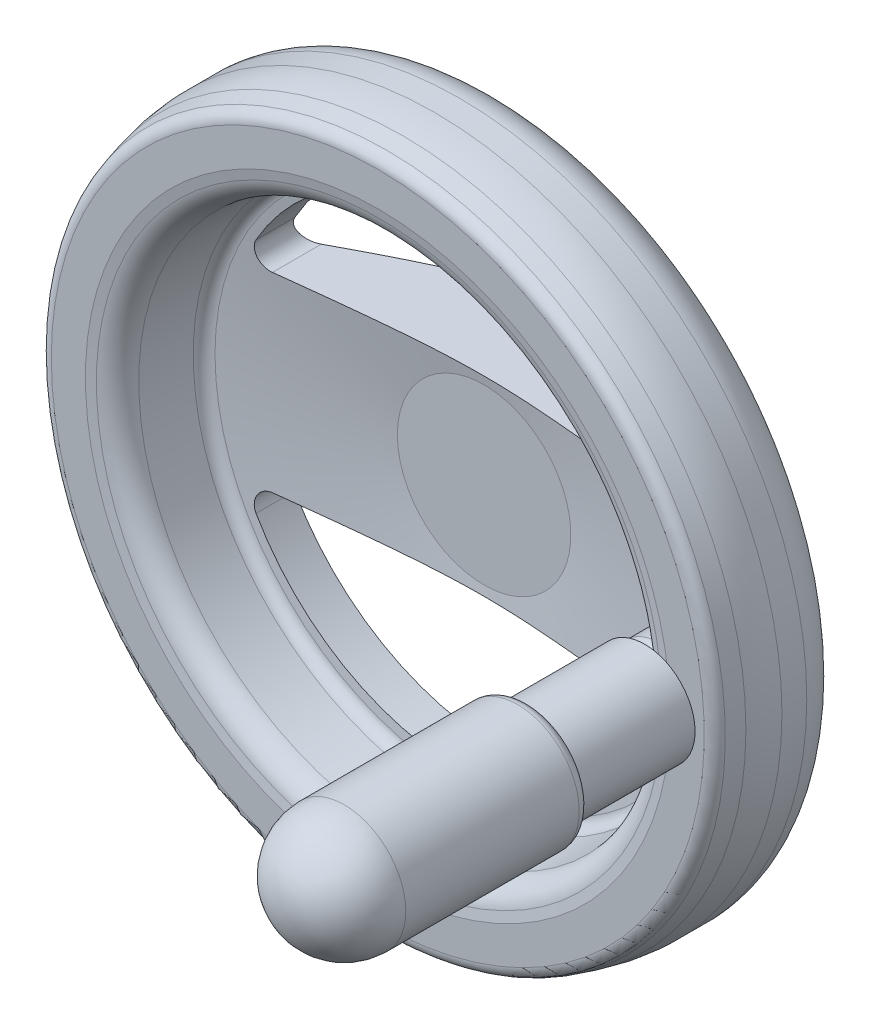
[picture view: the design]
ISO-10303-21;
HEADER;
FILE_DESCRIPTION(('STEP AP214'),'2;1');
FILE_NAME('part.step','',(''),(''),'','','');
FILE_SCHEMA(('AUTOMOTIVE_DESIGN { 1 0 10303 214 1 1 1 1 }'));
ENDSEC;
DATA;
#1=APPLICATION_CONTEXT('core data for automotive mechanical design processes');
#2=APPLICATION_PROTOCOL_DEFINITION('international standard','automotive_design',2000,#1);
#3=PRODUCT_CONTEXT('',#1,'mechanical');
#4=PRODUCT('Part','Part','',(#3));
#5=PRODUCT_RELATED_PRODUCT_CATEGORY('part','',(#4));
#6=PRODUCT_DEFINITION_FORMATION('','',#4);
#7=PRODUCT_DEFINITION_CONTEXT('part definition',#1,'design');
#8=PRODUCT_DEFINITION('design','',#6,#7);
#9=PRODUCT_DEFINITION_SHAPE('','',#8);
#10=(LENGTH_UNIT() NAMED_UNIT(*) SI_UNIT(.MILLI.,.METRE.));
#11=(NAMED_UNIT(*) PLANE_ANGLE_UNIT() SI_UNIT($,.RADIAN.));
#12=(NAMED_UNIT(*) SI_UNIT($,.STERADIAN.) SOLID_ANGLE_UNIT());
#13=UNCERTAINTY_MEASURE_WITH_UNIT(LENGTH_MEASURE(1.E-05),#10,'distance_accuracy_value','');
#14=(GEOMETRIC_REPRESENTATION_CONTEXT(3) GLOBAL_UNCERTAINTY_ASSIGNED_CONTEXT((#13)) GLOBAL_UNIT_ASSIGNED_CONTEXT((#10,
#11,#12)) REPRESENTATION_CONTEXT('',''));
#15=CARTESIAN_POINT('',(0.,0.,0.));
#16=DIRECTION('',(0.,0.,1.));
#17=DIRECTION('',(1.,0.,0.));
#18=AXIS2_PLACEMENT_3D('',#15,#16,#17);
#19=CARTESIAN_POINT('',(-3.6875,0.,22.));
#20=DIRECTION('',(0.,0.,-1.));
#21=DIRECTION('',(0.,1.,0.));
#22=AXIS2_PLACEMENT_3D('',#19,#20,#21);
#23=PLANE('',#22);
#24=CARTESIAN_POINT('',(0.,0.,21.9999999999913));
#25=DIRECTION('',(0.,0.,1.));
#26=DIRECTION('',(0.,-1.,0.));
#27=AXIS2_PLACEMENT_3D('',#24,#25,#26);
#28=CIRCLE('',#27,7.37499999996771);
#29=CARTESIAN_POINT('',(0.,-7.37499999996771,21.9999999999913));
#30=VERTEX_POINT('',#29);
#31=EDGE_CURVE('E227',#30,#30,#28,.F.);
#32=ORIENTED_EDGE('',*,*,#31,.T.);
#33=EDGE_LOOP('',(#32));
#34=FACE_BOUND('',#33,.T.);
#35=ADVANCED_FACE('F14',(#34),#23,.T.);
#36=CARTESIAN_POINT('',(0.,0.,22.0000000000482));
#37=DIRECTION('',(0.,0.,1.));
#38=DIRECTION('',(0.,-1.,0.));
#39=AXIS2_PLACEMENT_3D('',#36,#37,#38);
#40=CONICAL_SURFACE('',#39,7.37500000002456,0.785398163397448);
#41=ORIENTED_EDGE('',*,*,#31,.F.);
#42=EDGE_LOOP('',(#41));
#43=FACE_BOUND('',#42,.T.);
#44=CARTESIAN_POINT('',(0.,0.,20.625));
#45=DIRECTION('',(0.,0.,1.));
#46=DIRECTION('',(-1.,0.,0.));
#47=AXIS2_PLACEMENT_3D('',#44,#45,#46);
#48=CIRCLE('',#47,6.);
#49=CARTESIAN_POINT('',(-6.,0.,20.625));
#50=VERTEX_POINT('',#49);
#51=EDGE_CURVE('E230',#50,#50,#48,.F.);
#52=ORIENTED_EDGE('',*,*,#51,.T.);
#53=EDGE_LOOP('',(#52));
#54=FACE_BOUND('',#53,.T.);
#55=ADVANCED_FACE('F810',(#43,#54),#40,.F.);
#56=CARTESIAN_POINT('',(0.,0.,10.4125));
#57=DIRECTION('',(0.,0.,1.));
#58=DIRECTION('',(-1.,0.,0.));
#59=AXIS2_PLACEMENT_3D('',#56,#57,#58);
#60=CYLINDRICAL_SURFACE('',#59,6.);
#61=ORIENTED_EDGE('',*,*,#51,.F.);
#62=EDGE_LOOP('',(#61));
#63=FACE_BOUND('',#62,.T.);
#64=CARTESIAN_POINT('',(0.,0.,0.199999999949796));
#65=DIRECTION('',(0.,0.,-1.));
#66=DIRECTION('',(-1.,0.,0.));
#67=AXIS2_PLACEMENT_3D('',#64,#65,#66);
#68=CIRCLE('',#67,6.00000000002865);
#69=CARTESIAN_POINT('',(-6.00000000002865,0.,0.199999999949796));
#70=VERTEX_POINT('',#69);
#71=EDGE_CURVE('E226',#70,#70,#68,.T.);
#72=ORIENTED_EDGE('',*,*,#71,.T.);
#73=EDGE_LOOP('',(#72));
#74=FACE_BOUND('',#73,.T.);
#75=ADVANCED_FACE('F815',(#63,#74),#60,.F.);
#76=CARTESIAN_POINT('',(0.,0.,-5.68429783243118E-11));
#77=DIRECTION('',(0.,0.,-1.));
#78=DIRECTION('',(1.,0.,0.));
#79=AXIS2_PLACEMENT_3D('',#76,#77,#78);
#80=CONICAL_SURFACE('',#79,6.20000000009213,0.785398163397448);
#81=ORIENTED_EDGE('',*,*,#71,.F.);
#82=EDGE_LOOP('',(#81));
#83=FACE_BOUND('',#82,.T.);
#84=CARTESIAN_POINT('',(0.,0.,-5.68421109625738E-11));
#85=DIRECTION('',(0.,0.,-1.));
#86=DIRECTION('',(1.,0.,0.));
#87=AXIS2_PLACEMENT_3D('',#84,#85,#86);
#88=CIRCLE('',#87,6.20000000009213);
#89=CARTESIAN_POINT('',(6.20000000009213,0.,-5.68421109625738E-11));
#90=VERTEX_POINT('',#89);
#91=EDGE_CURVE('E223',#90,#90,#88,.F.);
#92=ORIENTED_EDGE('',*,*,#91,.F.);
#93=EDGE_LOOP('',(#92));
#94=FACE_BOUND('',#93,.T.);
#95=ADVANCED_FACE('F821',(#83,#94),#80,.F.);
#96=CARTESIAN_POINT('',(-8.6,0.,0.));
#97=DIRECTION('',(0.,0.,-1.));
#98=DIRECTION('',(1.,0.,0.));
#99=AXIS2_PLACEMENT_3D('',#96,#97,#98);
#100=PLANE('',#99);
#101=CARTESIAN_POINT('',(0.,0.,0.));
#102=DIRECTION('',(0.,0.,1.));
#103=DIRECTION('',(-1.,0.,0.));
#104=AXIS2_PLACEMENT_3D('',#101,#102,#103);
#105=CIRCLE('',#104,11.);
#106=CARTESIAN_POINT('',(-11.,0.,0.));
#107=VERTEX_POINT('',#106);
#108=EDGE_CURVE('E188',#107,#107,#105,.T.);
#109=ORIENTED_EDGE('',*,*,#108,.F.);
#110=EDGE_LOOP('',(#109));
#111=FACE_BOUND('',#110,.T.);
#112=ORIENTED_EDGE('',*,*,#91,.T.);
#113=EDGE_LOOP('',(#112));
#114=FACE_BOUND('',#113,.T.);
#115=ADVANCED_FACE('F824',(#111,#114),#100,.T.);
#116=CARTESIAN_POINT('',(0.,0.,0.1));
#117=DIRECTION('',(0.,0.,1.));
#118=DIRECTION('',(-1.,0.,0.));
#119=AXIS2_PLACEMENT_3D('',#116,#117,#118);
#120=CYLINDRICAL_SURFACE('',#119,11.);
#121=ORIENTED_EDGE('',*,*,#108,.T.);
#122=EDGE_LOOP('',(#121));
#123=FACE_BOUND('',#122,.T.);
#124=CARTESIAN_POINT('',(0.,0.,0.2));
#125=DIRECTION('',(0.,0.,1.));
#126=DIRECTION('',(-1.,0.,0.));
#127=AXIS2_PLACEMENT_3D('',#124,#125,#126);
#128=CIRCLE('',#127,11.);
#129=CARTESIAN_POINT('',(-11.,0.,0.2));
#130=VERTEX_POINT('',#129);
#131=EDGE_CURVE('E169',#130,#130,#128,.T.);
#132=ORIENTED_EDGE('',*,*,#131,.F.);
#133=EDGE_LOOP('',(#132));
#134=FACE_BOUND('',#133,.T.);
#135=ADVANCED_FACE('F212',(#123,#134),#120,.T.);
#136=CARTESIAN_POINT('',(-13.,0.,0.2));
#137=DIRECTION('',(0.,0.,-1.));
#138=DIRECTION('',(0.,1.,0.));
#139=AXIS2_PLACEMENT_3D('',#136,#137,#138);
#140=PLANE('',#139);
#141=CARTESIAN_POINT('',(0.,0.,0.2));
#142=DIRECTION('',(0.,0.,1.));
#143=DIRECTION('',(0.,-1.,0.));
#144=AXIS2_PLACEMENT_3D('',#141,#142,#143);
#145=CIRCLE('',#144,15.);
#146=CARTESIAN_POINT('',(0.,-15.,0.2));
#147=VERTEX_POINT('',#146);
#148=CARTESIAN_POINT('',(0.,15.,0.2));
#149=VERTEX_POINT('',#148);
#150=EDGE_CURVE('E572',#147,#149,#145,.T.);
#151=ORIENTED_EDGE('',*,*,#150,.F.);
#152=CARTESIAN_POINT('',(0.,0.,0.2));
#153=DIRECTION('',(0.,0.,1.));
#154=DIRECTION('',(-1.,0.,0.));
#155=AXIS2_PLACEMENT_3D('',#152,#153,#154);
#156=CIRCLE('',#155,15.);
#157=CARTESIAN_POINT('',(-15.,0.,0.2));
#158=VERTEX_POINT('',#157);
#159=EDGE_CURVE('E569',#158,#147,#156,.T.);
#160=ORIENTED_EDGE('',*,*,#159,.F.);
#161=CARTESIAN_POINT('',(0.,0.,0.2));
#162=DIRECTION('',(0.,0.,1.));
#163=DIRECTION('',(0.,1.,0.));
#164=AXIS2_PLACEMENT_3D('',#161,#162,#163);
#165=CIRCLE('',#164,15.);
#166=EDGE_CURVE('E537',#149,#158,#165,.T.);
#167=ORIENTED_EDGE('',*,*,#166,.F.);
#168=EDGE_LOOP('',(#151,#160,#167));
#169=FACE_BOUND('',#168,.T.);
#170=ORIENTED_EDGE('',*,*,#131,.T.);
#171=EDGE_LOOP('',(#170));
#172=FACE_BOUND('',#171,.T.);
#173=ADVANCED_FACE('F543',(#169,#172),#140,.T.);
#174=CARTESIAN_POINT('',(0.,0.,0.7));
#175=DIRECTION('',(0.,0.,-1.));
#176=DIRECTION('',(0.,1.,0.));
#177=AXIS2_PLACEMENT_3D('',#174,#175,#176);
#178=TOROIDAL_SURFACE('',#177,15.,0.5);
#179=CARTESIAN_POINT('',(0.,0.,0.7));
#180=DIRECTION('',(0.,0.,1.));
#181=DIRECTION('',(-1.,0.,0.));
#182=AXIS2_PLACEMENT_3D('',#179,#180,#181);
#183=CIRCLE('',#182,15.5);
#184=CARTESIAN_POINT('',(-15.5,0.,0.7));
#185=VERTEX_POINT('',#184);
#186=EDGE_CURVE('E605',#185,#185,#183,.T.);
#187=ORIENTED_EDGE('',*,*,#186,.F.);
#188=EDGE_LOOP('',(#187));
#189=FACE_BOUND('',#188,.T.);
#190=ORIENTED_EDGE('',*,*,#150,.T.);
#191=ORIENTED_EDGE('',*,*,#166,.T.);
#192=ORIENTED_EDGE('',*,*,#159,.T.);
#193=EDGE_LOOP('',(#190,#191,#192));
#194=FACE_BOUND('',#193,.T.);
#195=ADVANCED_FACE('F551',(#189,#194),#178,.T.);
#196=CARTESIAN_POINT('',(0.,0.,3.1));
#197=DIRECTION('',(0.,0.,1.));
#198=DIRECTION('',(-1.,0.,0.));
#199=AXIS2_PLACEMENT_3D('',#196,#197,#198);
#200=CYLINDRICAL_SURFACE('',#199,15.5);
#201=ORIENTED_EDGE('',*,*,#186,.T.);
#202=EDGE_LOOP('',(#201));
#203=FACE_BOUND('',#202,.T.);
#204=CARTESIAN_POINT('',(0.,0.,5.5));
#205=DIRECTION('',(0.,0.,1.));
#206=DIRECTION('',(-1.,0.,0.));
#207=AXIS2_PLACEMENT_3D('',#204,#205,#206);
#208=CIRCLE('',#207,15.5);
#209=CARTESIAN_POINT('',(-15.5,0.,5.5));
#210=VERTEX_POINT('',#209);
#211=EDGE_CURVE('E922',#210,#210,#208,.T.);
#212=ORIENTED_EDGE('',*,*,#211,.F.);
#213=EDGE_LOOP('',(#212));
#214=FACE_BOUND('',#213,.T.);
#215=ADVANCED_FACE('F259',(#203,#214),#200,.T.);
#216=CARTESIAN_POINT('',(0.,0.,29.3333333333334));
#217=DIRECTION('',(0.,0.,-1.));
#218=DIRECTION('',(0.,1.,0.));
#219=AXIS2_PLACEMENT_3D('',#216,#217,#218);
#220=TOROIDAL_SURFACE('',#219,54.6666666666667,7.33333333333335);
#221=CARTESIAN_POINT('',(0.,0.,22.));
#222=DIRECTION('',(0.,0.,1.));
#223=DIRECTION('',(0.,-1.,0.));
#224=AXIS2_PLACEMENT_3D('',#221,#222,#223);
#225=CIRCLE('',#224,54.6666666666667);
#226=CARTESIAN_POINT('',(0.,54.6666666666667,22.));
#227=VERTEX_POINT('',#226);
#228=CARTESIAN_POINT('',(0.,-54.6666666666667,22.));
#229=VERTEX_POINT('',#228);
#230=EDGE_CURVE('E239',#227,#229,#225,.F.);
#231=ORIENTED_EDGE('',*,*,#230,.F.);
#232=CARTESIAN_POINT('',(0.,0.,22.));
#233=DIRECTION('',(0.,0.,1.));
#234=DIRECTION('',(0.,1.,0.));
#235=AXIS2_PLACEMENT_3D('',#232,#233,#234);
#236=CIRCLE('',#235,54.6666666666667);
#237=CARTESIAN_POINT('',(-54.6666666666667,0.,22.));
#238=VERTEX_POINT('',#237);
#239=EDGE_CURVE('E287',#238,#227,#236,.F.);
#240=ORIENTED_EDGE('',*,*,#239,.F.);
#241=CARTESIAN_POINT('',(0.,0.,22.));
#242=DIRECTION('',(0.,0.,1.));
#243=DIRECTION('',(-1.,0.,0.));
#244=AXIS2_PLACEMENT_3D('',#241,#242,#243);
#245=CIRCLE('',#244,54.6666666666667);
#246=EDGE_CURVE('E276',#229,#238,#245,.F.);
#247=ORIENTED_EDGE('',*,*,#246,.F.);
#248=EDGE_LOOP('',(#231,#240,#247));
#249=FACE_BOUND('',#248,.T.);
#250=CARTESIAN_POINT('',(0.,0.,29.3333333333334));
#251=DIRECTION('',(0.,0.,-1.));
#252=DIRECTION('',(0.,1.,0.));
#253=AXIS2_PLACEMENT_3D('',#250,#251,#252);
#254=CIRCLE('',#253,62.);
#255=CARTESIAN_POINT('',(0.,62.,29.3333333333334));
#256=VERTEX_POINT('',#255);
#257=EDGE_CURVE('E300',#256,#256,#254,.T.);
#258=ORIENTED_EDGE('',*,*,#257,.T.);
#259=EDGE_LOOP('',(#258));
#260=FACE_BOUND('',#259,.T.);
#261=ADVANCED_FACE('F247',(#249,#260),#220,.T.);
#262=CARTESIAN_POINT('',(0.,0.,31.5518225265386));
#263=DIRECTION('',(0.,0.,1.));
#264=DIRECTION('',(-1.,0.,0.));
#265=AXIS2_PLACEMENT_3D('',#262,#263,#264);
#266=CYLINDRICAL_SURFACE('',#265,62.);
#267=CARTESIAN_POINT('',(0.,0.,33.770311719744));
#268=DIRECTION('',(0.,0.,1.));
#269=DIRECTION('',(-1.,0.,0.));
#270=AXIS2_PLACEMENT_3D('',#267,#268,#269);
#271=CIRCLE('',#270,62.);
#272=CARTESIAN_POINT('',(-62.,0.,33.770311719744));
#273=VERTEX_POINT('',#272);
#274=EDGE_CURVE('E931',#273,#273,#271,.F.);
#275=ORIENTED_EDGE('',*,*,#274,.T.);
#276=EDGE_LOOP('',(#275));
#277=FACE_BOUND('',#276,.T.);
#278=ORIENTED_EDGE('',*,*,#257,.F.);
#279=EDGE_LOOP('',(#278));
#280=FACE_BOUND('',#279,.T.);
#281=ADVANCED_FACE('F258',(#277,#280),#266,.T.);
#282=CARTESIAN_POINT('',(0.,0.,17.6));
#283=DIRECTION('',(0.,0.,-1.));
#284=DIRECTION('',(0.,1.,0.));
#285=AXIS2_PLACEMENT_3D('',#282,#283,#284);
#286=TOROIDAL_SURFACE('',#285,44.3996566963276,4.3999999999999);
#287=CARTESIAN_POINT('',(0.,0.,21.6825238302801));
#288=DIRECTION('',(0.,0.,-1.));
#289=DIRECTION('',(0.,1.,0.));
#290=AXIS2_PLACEMENT_3D('',#287,#288,#289);
#291=CIRCLE('',#290,42.7586206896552);
#292=CARTESIAN_POINT('',(-37.1502056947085,21.1698337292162,21.6825238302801));
#293=VERTEX_POINT('',#292);
#294=CARTESIAN_POINT('',(37.1502057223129,21.1698336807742,21.6825238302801));
#295=VERTEX_POINT('',#294);
#296=EDGE_CURVE('E310',#293,#295,#291,.T.);
#297=ORIENTED_EDGE('',*,*,#296,.F.);
#298=CARTESIAN_POINT('',(-37.4658577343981,19.305357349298,21.3797465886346));
#299=CARTESIAN_POINT('',(-37.477991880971,19.3710035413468,21.4040912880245));
#300=CARTESIAN_POINT('',(-37.4878240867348,19.4377213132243,21.4266745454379));
#301=CARTESIAN_POINT('',(-37.5026165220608,19.572709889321,21.4685151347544));
#302=CARTESIAN_POINT('',(-37.5075775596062,19.6409804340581,21.4877730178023));
#303=CARTESIAN_POINT('',(-37.5123633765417,19.7784953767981,21.5231648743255));
#304=CARTESIAN_POINT('',(-37.5121889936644,19.8477396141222,21.5392993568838));
#305=CARTESIAN_POINT('',(-37.5065616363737,19.9866080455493,21.5686657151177));
#306=CARTESIAN_POINT('',(-37.5011087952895,20.0562322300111,21.5818976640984));
#307=CARTESIAN_POINT('',(-37.476687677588,20.2648369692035,21.6175724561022));
#308=CARTESIAN_POINT('',(-37.4496606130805,20.4036511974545,21.6360193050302));
#309=CARTESIAN_POINT('',(-37.3743306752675,20.6760722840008,21.6636613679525));
#310=CARTESIAN_POINT('',(-37.3260665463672,20.8096881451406,21.6728733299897));
#311=CARTESIAN_POINT('',(-37.250048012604,20.9782012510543,21.6794580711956));
#312=CARTESIAN_POINT('',(-37.2313331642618,21.0172035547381,21.6806098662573));
#313=CARTESIAN_POINT('',(-37.1921088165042,21.0942437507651,21.6821419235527));
#314=CARTESIAN_POINT('',(-37.1716017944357,21.1322828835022,21.6825232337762));
#315=CARTESIAN_POINT('',(-37.1502056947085,21.1698337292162,21.6825238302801));
#316=B_SPLINE_CURVE_WITH_KNOTS('',3,(#298,#299,#300,#301,#302,#303,#304,#305,#306,#307,#308,
#309,#310,#311,#312,#313,#314,#315),.UNSPECIFIED.,.F.,.F.,(4,2,2,2,2,2,2,2,4),(0.,
0.213099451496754,0.426163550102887,0.639192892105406,0.852216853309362,1.27795500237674,
1.70291964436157,1.83270697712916,1.96231765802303),.UNSPECIFIED.);
#317=CARTESIAN_POINT('',(-37.465857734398,19.3053573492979,21.3797465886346));
#318=VERTEX_POINT('',#317);
#319=EDGE_CURVE('E350',#318,#293,#316,.T.);
#320=ORIENTED_EDGE('',*,*,#319,.F.);
#321=CARTESIAN_POINT('',(0.,0.,21.3797465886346));
#322=DIRECTION('',(0.,0.,-1.));
#323=DIRECTION('',(0.,1.,0.));
#324=AXIS2_PLACEMENT_3D('',#321,#322,#323);
#325=CIRCLE('',#324,42.1472100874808);
#326=CARTESIAN_POINT('',(-37.465857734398,-19.3053573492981,21.3797465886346));
#327=VERTEX_POINT('',#326);
#328=EDGE_CURVE('E334',#327,#318,#325,.T.);
#329=ORIENTED_EDGE('',*,*,#328,.F.);
#330=CARTESIAN_POINT('',(-37.1502057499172,-21.1698336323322,21.68252383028));
#331=CARTESIAN_POINT('',(-37.1857308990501,-21.1075115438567,21.6825145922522));
#332=CARTESIAN_POINT('',(-37.2188054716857,-21.0437931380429,21.6814700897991));
#333=CARTESIAN_POINT('',(-37.2798689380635,-20.9140276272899,21.6772435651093));
#334=CARTESIAN_POINT('',(-37.3078575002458,-20.8479803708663,21.6740614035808));
#335=CARTESIAN_POINT('',(-37.3585995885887,-20.713924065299,21.6654858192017));
#336=CARTESIAN_POINT('',(-37.3813448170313,-20.6459120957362,21.660088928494));
#337=CARTESIAN_POINT('',(-37.4214185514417,-20.5085362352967,21.646954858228));
#338=CARTESIAN_POINT('',(-37.4387474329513,-20.4391724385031,21.6392178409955));
#339=CARTESIAN_POINT('',(-37.4679400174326,-20.2995236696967,21.6212232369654));
#340=CARTESIAN_POINT('',(-37.4797961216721,-20.2292375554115,21.6109621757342));
#341=CARTESIAN_POINT('',(-37.4980012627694,-20.0884021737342,21.5877222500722));
#342=CARTESIAN_POINT('',(-37.5043504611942,-20.0178529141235,21.5747434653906));
#343=CARTESIAN_POINT('',(-37.5116013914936,-19.8772479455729,21.5458799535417));
#344=CARTESIAN_POINT('',(-37.5125161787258,-19.8071914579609,21.5300022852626));
#345=CARTESIAN_POINT('',(-37.5090819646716,-19.6680289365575,21.4950986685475));
#346=CARTESIAN_POINT('',(-37.5047358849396,-19.5989223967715,21.4760744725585));
#347=CARTESIAN_POINT('',(-37.494063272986,-19.4924910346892,21.4438281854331));
#348=CARTESIAN_POINT('',(-37.4894634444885,-19.4546310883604,21.4317625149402));
#349=CARTESIAN_POINT('',(-37.4787676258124,-19.379522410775,21.4065646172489));
#350=CARTESIAN_POINT('',(-37.4726730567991,-19.342273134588,21.393433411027));
#351=CARTESIAN_POINT('',(-37.465857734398,-19.3053573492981,21.3797465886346));
#352=B_SPLINE_CURVE_WITH_KNOTS('',3,(#330,#331,#332,#333,#334,#335,#336,#337,#338,#339,#340,
#341,#342,#343,#344,#345,#346,#347,#348,#349,#350,#351),.UNSPECIFIED.,.F.,.F.,(4,2,2,2,2,2,2,2,
2,2,4),(0.,0.215145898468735,0.43030581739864,0.645803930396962,0.861287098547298,
1.07706856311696,1.29284369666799,1.50810025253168,1.72323732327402,1.84319972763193,
1.96304851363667),.UNSPECIFIED.);
#353=CARTESIAN_POINT('',(-37.1502057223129,-21.1698336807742,21.6825238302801));
#354=VERTEX_POINT('',#353);
#355=EDGE_CURVE('E342',#354,#327,#352,.T.);
#356=ORIENTED_EDGE('',*,*,#355,.F.);
#357=CARTESIAN_POINT('',(0.,0.,21.6825238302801));
#358=DIRECTION('',(0.,0.,-1.));
#359=DIRECTION('',(0.,1.,0.));
#360=AXIS2_PLACEMENT_3D('',#357,#358,#359);
#361=CIRCLE('',#360,42.7586206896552);
#362=CARTESIAN_POINT('',(37.1502056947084,-21.1698337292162,21.68252383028));
#363=VERTEX_POINT('',#362);
#364=EDGE_CURVE('E297',#363,#354,#361,.T.);
#365=ORIENTED_EDGE('',*,*,#364,.F.);
#366=CARTESIAN_POINT('',(37.465857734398,-19.305357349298,21.3797465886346));
#367=CARTESIAN_POINT('',(37.4779918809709,-19.3710035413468,21.4040912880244));
#368=CARTESIAN_POINT('',(37.4878240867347,-19.4377213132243,21.4266745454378));
#369=CARTESIAN_POINT('',(37.5026165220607,-19.572709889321,21.4685151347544));
#370=CARTESIAN_POINT('',(37.5075775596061,-19.6409804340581,21.4877730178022));
#371=CARTESIAN_POINT('',(37.5123633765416,-19.7784953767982,21.5231648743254));
#372=CARTESIAN_POINT('',(37.5121889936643,-19.8477396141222,21.5392993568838));
#373=CARTESIAN_POINT('',(37.5065616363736,-19.9866080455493,21.5686657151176));
#374=CARTESIAN_POINT('',(37.5011087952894,-20.0562322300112,21.5818976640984));
#375=CARTESIAN_POINT('',(37.4766876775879,-20.2648369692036,21.6175724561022));
#376=CARTESIAN_POINT('',(37.4496606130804,-20.4036511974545,21.6360193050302));
#377=CARTESIAN_POINT('',(37.3743306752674,-20.6760722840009,21.6636613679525));
#378=CARTESIAN_POINT('',(37.326066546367,-20.8096881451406,21.6728733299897));
#379=CARTESIAN_POINT('',(37.2500480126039,-20.9782012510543,21.6794580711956));
#380=CARTESIAN_POINT('',(37.2313331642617,-21.0172035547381,21.6806098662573));
#381=CARTESIAN_POINT('',(37.1921088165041,-21.0942437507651,21.6821419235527));
#382=CARTESIAN_POINT('',(37.1716017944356,-21.1322828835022,21.6825232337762));
#383=CARTESIAN_POINT('',(37.1502056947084,-21.1698337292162,21.68252383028));
#384=B_SPLINE_CURVE_WITH_KNOTS('',3,(#366,#367,#368,#369,#370,#371,#372,#373,#374,#375,#376,
#377,#378,#379,#380,#381,#382,#383),.UNSPECIFIED.,.F.,.F.,(4,2,2,2,2,2,2,2,4),(0.,
0.213099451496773,0.426163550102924,0.639192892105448,0.852216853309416,1.2779550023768,
1.70291964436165,1.83270697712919,1.96231765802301),.UNSPECIFIED.);
#385=CARTESIAN_POINT('',(37.465857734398,-19.305357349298,21.3797465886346));
#386=VERTEX_POINT('',#385);
#387=EDGE_CURVE('E301',#386,#363,#384,.T.);
#388=ORIENTED_EDGE('',*,*,#387,.F.);
#389=CARTESIAN_POINT('',(0.,0.,21.3797465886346));
#390=DIRECTION('',(0.,0.,-1.));
#391=DIRECTION('',(0.,1.,0.));
#392=AXIS2_PLACEMENT_3D('',#389,#390,#391);
#393=CIRCLE('',#392,42.1472100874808);
#394=CARTESIAN_POINT('',(37.4658577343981,19.305357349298,21.3797465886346));
#395=VERTEX_POINT('',#394);
#396=EDGE_CURVE('E304',#395,#386,#393,.T.);
#397=ORIENTED_EDGE('',*,*,#396,.F.);
#398=CARTESIAN_POINT('',(37.1502057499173,21.1698336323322,21.6825238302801));
#399=CARTESIAN_POINT('',(37.1857308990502,21.1075115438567,21.6825145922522));
#400=CARTESIAN_POINT('',(37.2188054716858,21.043793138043,21.6814700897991));
#401=CARTESIAN_POINT('',(37.2798689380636,20.9140276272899,21.6772435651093));
#402=CARTESIAN_POINT('',(37.3078575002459,20.8479803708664,21.6740614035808));
#403=CARTESIAN_POINT('',(37.3585995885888,20.713924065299,21.6654858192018));
#404=CARTESIAN_POINT('',(37.3813448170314,20.6459120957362,21.660088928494));
#405=CARTESIAN_POINT('',(37.4214185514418,20.5085362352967,21.6469548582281));
#406=CARTESIAN_POINT('',(37.4387474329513,20.4391724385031,21.6392178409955));
#407=CARTESIAN_POINT('',(37.4679400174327,20.2995236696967,21.6212232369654));
#408=CARTESIAN_POINT('',(37.4797961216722,20.2292375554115,21.6109621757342));
#409=CARTESIAN_POINT('',(37.4980012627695,20.0884021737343,21.5877222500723));
#410=CARTESIAN_POINT('',(37.5043504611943,20.0178529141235,21.5747434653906));
#411=CARTESIAN_POINT('',(37.5116013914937,19.877247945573,21.5458799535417));
#412=CARTESIAN_POINT('',(37.5125161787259,19.807191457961,21.5300022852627));
#413=CARTESIAN_POINT('',(37.5090819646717,19.6680289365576,21.4950986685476));
#414=CARTESIAN_POINT('',(37.5047358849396,19.5989223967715,21.4760744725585));
#415=CARTESIAN_POINT('',(37.4940632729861,19.4924910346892,21.4438281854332));
#416=CARTESIAN_POINT('',(37.4894634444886,19.4546310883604,21.4317625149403));
#417=CARTESIAN_POINT('',(37.4787676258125,19.3795224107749,21.4065646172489));
#418=CARTESIAN_POINT('',(37.4726730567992,19.3422731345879,21.393433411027));
#419=CARTESIAN_POINT('',(37.4658577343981,19.305357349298,21.3797465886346));
#420=B_SPLINE_CURVE_WITH_KNOTS('',3,(#398,#399,#400,#401,#402,#403,#404,#405,#406,#407,#408,
#409,#410,#411,#412,#413,#414,#415,#416,#417,#418,#419),.UNSPECIFIED.,.F.,.F.,(4,2,2,2,2,2,2,2,
2,2,4),(0.,0.215145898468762,0.430305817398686,0.645803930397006,0.861287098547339,
1.07706856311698,1.29284369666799,1.50810025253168,1.72323732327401,1.843199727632,
1.96304851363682),.UNSPECIFIED.);
#421=EDGE_CURVE('E307',#295,#395,#420,.T.);
#422=ORIENTED_EDGE('',*,*,#421,.F.);
#423=EDGE_LOOP('',(#297,#320,#329,#356,#365,#388,#397,#422));
#424=FACE_BOUND('',#423,.T.);
#425=CARTESIAN_POINT('',(0.,0.,21.9999999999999));
#426=DIRECTION('',(0.,0.,-1.));
#427=DIRECTION('',(0.,-1.,0.));
#428=AXIS2_PLACEMENT_3D('',#425,#426,#427);
#429=CIRCLE('',#428,44.3996566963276);
#430=CARTESIAN_POINT('',(0.,44.3996566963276,22.));
#431=VERTEX_POINT('',#430);
#432=CARTESIAN_POINT('',(0.,-44.3996566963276,22.));
#433=VERTEX_POINT('',#432);
#434=EDGE_CURVE('E986',#431,#433,#429,.F.);
#435=ORIENTED_EDGE('',*,*,#434,.F.);
#436=CARTESIAN_POINT('',(0.,0.,21.9999999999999));
#437=DIRECTION('',(0.,0.,-1.));
#438=DIRECTION('',(0.,1.,0.));
#439=AXIS2_PLACEMENT_3D('',#436,#437,#438);
#440=CIRCLE('',#439,44.3996566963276);
#441=CARTESIAN_POINT('',(44.2383861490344,3.78083399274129,22.));
#442=VERTEX_POINT('',#441);
#443=EDGE_CURVE('E488',#442,#431,#440,.F.);
#444=ORIENTED_EDGE('',*,*,#443,.F.);
#445=CARTESIAN_POINT('',(0.,0.,21.9999999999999));
#446=DIRECTION('',(0.,0.,-1.));
#447=DIRECTION('',(0.996367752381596,0.0851545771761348,0.));
#448=AXIS2_PLACEMENT_3D('',#445,#446,#447);
#449=CIRCLE('',#448,44.3996566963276);
#450=CARTESIAN_POINT('',(44.2383861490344,-3.78083399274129,22.));
#451=VERTEX_POINT('',#450);
#452=EDGE_CURVE('E313',#451,#442,#449,.F.);
#453=ORIENTED_EDGE('',*,*,#452,.F.);
#454=CARTESIAN_POINT('',(0.,0.,21.9999999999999));
#455=DIRECTION('',(0.,0.,-1.));
#456=DIRECTION('',(0.996367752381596,-0.0851545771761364,0.));
#457=AXIS2_PLACEMENT_3D('',#454,#455,#456);
#458=CIRCLE('',#457,44.3996566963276);
#459=EDGE_CURVE('E322',#433,#451,#458,.F.);
#460=ORIENTED_EDGE('',*,*,#459,.F.);
#461=EDGE_LOOP('',(#435,#444,#453,#460));
#462=FACE_BOUND('',#461,.T.);
#463=ADVANCED_FACE('F262',(#424,#462),#286,.F.);
#464=CARTESIAN_POINT('',(0.,0.,21.3797465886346));
#465=DIRECTION('',(0.,0.,1.));
#466=DIRECTION('',(-1.,0.,0.));
#467=AXIS2_PLACEMENT_3D('',#464,#465,#466);
#468=CONICAL_SURFACE('',#467,42.1472100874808,1.03337831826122);
#469=ORIENTED_EDGE('',*,*,#211,.T.);
#470=EDGE_LOOP('',(#469));
#471=FACE_BOUND('',#470,.T.);
#472=CARTESIAN_POINT('',(-34.7560813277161,-17.05,19.3331471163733));
#473=CARTESIAN_POINT('',(-34.9642160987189,-17.0500388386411,19.4445654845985));
#474=CARTESIAN_POINT('',(-35.1694190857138,-17.0735554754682,19.5606672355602));
#475=CARTESIAN_POINT('',(-35.5667554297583,-17.164089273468,19.7972740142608));
#476=CARTESIAN_POINT('',(-35.7589160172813,-17.2310125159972,19.9177690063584));
#477=CARTESIAN_POINT('',(-36.099678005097,-17.3933837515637,20.1427185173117));
#478=CARTESIAN_POINT('',(-36.250675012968,-17.4838625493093,20.2471778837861));
#479=CARTESIAN_POINT('',(-36.5340722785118,-17.6930027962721,20.4534650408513));
#480=CARTESIAN_POINT('',(-36.6664589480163,-17.8116846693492,20.5552908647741));
#481=CARTESIAN_POINT('',(-36.9097263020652,-18.0770520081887,20.7549142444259));
#482=CARTESIAN_POINT('',(-37.0202464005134,-18.2241386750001,20.8526261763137));
#483=CARTESIAN_POINT('',(-37.1636021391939,-18.4618665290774,20.9920574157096));
#484=CARTESIAN_POINT('',(-37.2076243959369,-18.5438882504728,21.0373125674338));
#485=CARTESIAN_POINT('',(-37.2875839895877,-18.7131623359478,21.1250514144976));
#486=CARTESIAN_POINT('',(-37.3235269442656,-18.8004110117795,21.1675370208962));
#487=CARTESIAN_POINT('',(-37.378644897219,-18.9568600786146,21.2389212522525));
#488=CARTESIAN_POINT('',(-37.3997621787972,-19.0250543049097,21.2685416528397));
#489=CARTESIAN_POINT('',(-37.4367840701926,-19.163634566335,21.3257302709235));
#490=CARTESIAN_POINT('',(-37.4526913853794,-19.2340194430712,21.353299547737));
#491=CARTESIAN_POINT('',(-37.465857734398,-19.3053573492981,21.3797465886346));
#492=B_SPLINE_CURVE_WITH_KNOTS('',3,(#472,#473,#474,#475,#476,#477,#478,#479,#480,#481,#482,
#483,#484,#485,#486,#487,#488,#489,#490,#491),.UNSPECIFIED.,.F.,.F.,(4,2,2,2,2,2,2,2,2,4),(0.,
0.706568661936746,1.41161360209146,2.0230154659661,2.63486144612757,3.25608193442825,
3.5662093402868,3.87612043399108,4.1077705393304,4.33930016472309),.UNSPECIFIED.);
#493=CARTESIAN_POINT('',(-34.7560813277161,-17.05,19.3331471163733));
#494=VERTEX_POINT('',#493);
#495=EDGE_CURVE('E1469',#494,#327,#492,.T.);
#496=ORIENTED_EDGE('',*,*,#495,.T.);
#497=ORIENTED_EDGE('',*,*,#328,.T.);
#498=CARTESIAN_POINT('',(-37.465857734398,19.3053573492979,21.3797465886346));
#499=CARTESIAN_POINT('',(-37.45063462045,19.2228937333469,21.3491732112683));
#500=CARTESIAN_POINT('',(-37.4317600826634,19.1417288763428,21.3171129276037));
#501=CARTESIAN_POINT('',(-37.3871473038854,18.9825042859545,21.2503457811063));
#502=CARTESIAN_POINT('',(-37.36141437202,18.9044422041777,21.2156409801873));
#503=CARTESIAN_POINT('',(-37.2748626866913,18.6763284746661,21.1083733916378));
#504=CARTESIAN_POINT('',(-37.2045125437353,18.5314258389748,21.0323117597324));
#505=CARTESIAN_POINT('',(-37.0423053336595,18.2591559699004,20.8736588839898));
#506=CARTESIAN_POINT('',(-36.9505105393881,18.1317396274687,20.7910869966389));
#507=CARTESIAN_POINT('',(-36.7485268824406,17.8957384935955,20.6211835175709));
#508=CARTESIAN_POINT('',(-36.6383094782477,17.7871834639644,20.5338446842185));
#509=CARTESIAN_POINT('',(-36.390008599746,17.5801946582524,20.346903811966));
#510=CARTESIAN_POINT('',(-36.2502031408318,17.4841040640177,20.2469929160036));
#511=CARTESIAN_POINT('',(-35.9559631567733,17.319233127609,20.0463793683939));
#512=CARTESIAN_POINT('',(-35.8015348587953,17.2504412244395,19.9456770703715));
#513=CARTESIAN_POINT('',(-35.5007531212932,17.1483578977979,19.7578042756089));
#514=CARTESIAN_POINT('',(-35.3556140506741,17.1118238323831,19.6704453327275));
#515=CARTESIAN_POINT('',(-35.0595338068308,17.0626556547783,19.4989251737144));
#516=CARTESIAN_POINT('',(-34.9085924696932,17.050022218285,19.4147640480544));
#517=CARTESIAN_POINT('',(-34.7560813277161,17.05,19.3331471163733));
#518=B_SPLINE_CURVE_WITH_KNOTS('',3,(#498,#499,#500,#501,#502,#503,#504,#505,#506,#507,#508,
#509,#510,#511,#512,#513,#514,#515,#516,#517),.UNSPECIFIED.,.F.,.F.,(4,2,2,2,2,2,2,2,2,4),(0.,
0.267554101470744,0.53490168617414,1.06663180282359,1.59683661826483,2.12787060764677,
2.71600119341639,3.30388243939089,3.82204375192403,4.34021971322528),.UNSPECIFIED.);
#519=CARTESIAN_POINT('',(-34.7560813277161,17.05,19.3331471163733));
#520=VERTEX_POINT('',#519);
#521=EDGE_CURVE('E380',#318,#520,#518,.T.);
#522=ORIENTED_EDGE('',*,*,#521,.T.);
#523=CARTESIAN_POINT('',(-34.7560813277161,17.05,19.3331471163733));
#524=CARTESIAN_POINT('',(-33.9725683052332,17.05,18.9140040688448));
#525=CARTESIAN_POINT('',(-33.187944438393,17.05,18.4969215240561));
#526=CARTESIAN_POINT('',(-31.6159567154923,17.05,17.667875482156));
#527=CARTESIAN_POINT('',(-30.8285927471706,17.05,17.2559121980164));
#528=CARTESIAN_POINT('',(-29.2495677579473,17.05,16.4375656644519));
#529=CARTESIAN_POINT('',(-28.4579022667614,17.05,16.0311910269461));
#530=CARTESIAN_POINT('',(-26.8707444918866,17.05,15.2260017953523));
#531=CARTESIAN_POINT('',(-26.0752522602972,17.05,14.827187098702));
#532=CARTESIAN_POINT('',(-24.4369579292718,17.05,14.0177947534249));
#533=CARTESIAN_POINT('',(-23.5939019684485,17.05,13.6077295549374));
#534=CARTESIAN_POINT('',(-21.9014905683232,17.05,12.8007036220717));
#535=CARTESIAN_POINT('',(-21.052134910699,17.05,12.4037433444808));
#536=CARTESIAN_POINT('',(-19.3461264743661,17.05,11.626846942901));
#537=CARTESIAN_POINT('',(-18.4894774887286,17.05,11.2469025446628));
#538=CARTESIAN_POINT('',(-17.1974661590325,17.05,10.6934878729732));
#539=CARTESIAN_POINT('',(-16.7656332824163,17.05,10.5117708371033));
#540=CARTESIAN_POINT('',(-15.8993625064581,17.05,10.1546646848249));
#541=CARTESIAN_POINT('',(-15.4649246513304,17.05,9.97927546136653));
#542=CARTESIAN_POINT('',(-14.5301471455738,17.05,9.61092120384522));
#543=CARTESIAN_POINT('',(-14.0293621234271,17.05,9.41908211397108));
#544=CARTESIAN_POINT('',(-13.0236598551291,17.05,9.04659617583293));
#545=CARTESIAN_POINT('',(-12.5187427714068,17.05,8.86594888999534));
#546=CARTESIAN_POINT('',(-11.5042481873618,17.05,8.51776826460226));
#547=CARTESIAN_POINT('',(-10.9946697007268,17.05,8.35023777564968));
#548=CARTESIAN_POINT('',(-9.9707227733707,17.05,8.0306459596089));
#549=CARTESIAN_POINT('',(-9.45635433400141,17.05,7.87858462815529));
#550=CARTESIAN_POINT('',(-7.92620850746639,17.05,7.45517806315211));
#551=CARTESIAN_POINT('',(-6.90297443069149,17.05,7.20940813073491));
#552=CARTESIAN_POINT('',(-5.3551607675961,17.05,6.90909796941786));
#553=CARTESIAN_POINT('',(-4.83711291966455,17.05,6.82039061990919));
#554=CARTESIAN_POINT('',(-3.79725745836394,17.05,6.66828978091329));
#555=CARTESIAN_POINT('',(-3.27544988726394,17.05,6.60489600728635));
#556=CARTESIAN_POINT('',(-2.21924330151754,17.05,6.50459293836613));
#557=CARTESIAN_POINT('',(-1.68479371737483,17.05,6.46821090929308));
#558=CARTESIAN_POINT('',(-0.614687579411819,17.05,6.42530779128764));
#559=CARTESIAN_POINT('',(-0.0790310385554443,17.05,6.41878638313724));
#560=CARTESIAN_POINT('',(0.991781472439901,17.05,6.43586040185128));
#561=CARTESIAN_POINT('',(1.52693745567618,17.05,6.45945501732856));
#562=CARTESIAN_POINT('',(2.5951483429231,17.05,6.53584590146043));
#563=CARTESIAN_POINT('',(3.12820319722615,17.05,6.58864285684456));
#564=CARTESIAN_POINT('',(4.20204910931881,17.05,6.72293286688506));
#565=CARTESIAN_POINT('',(4.74276684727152,17.05,6.8050065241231));
#566=CARTESIAN_POINT('',(5.81967745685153,17.05,6.99488444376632));
#567=CARTESIAN_POINT('',(6.35586984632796,17.05,7.10269141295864));
#568=CARTESIAN_POINT('',(7.42338587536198,17.05,7.34102353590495));
#569=CARTESIAN_POINT('',(7.95470727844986,17.05,7.4715586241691));
#570=CARTESIAN_POINT('',(9.0121030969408,17.05,7.75225748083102));
#571=CARTESIAN_POINT('',(9.53817749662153,17.05,7.90242130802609));
#572=CARTESIAN_POINT('',(10.621187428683,17.05,8.23042811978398));
#573=CARTESIAN_POINT('',(11.1777598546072,17.05,8.40946399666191));
#574=CARTESIAN_POINT('',(12.2854805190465,17.05,8.78365072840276));
#575=CARTESIAN_POINT('',(12.8366283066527,17.05,8.97880291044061));
#576=CARTESIAN_POINT('',(13.9341401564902,17.05,9.38267214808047));
#577=CARTESIAN_POINT('',(14.4805023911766,17.05,9.59139414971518));
#578=CARTESIAN_POINT('',(15.5687390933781,17.05,10.0201486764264));
#579=CARTESIAN_POINT('',(16.1106136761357,17.05,10.2401809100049));
#580=CARTESIAN_POINT('',(17.1914207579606,17.05,10.6901844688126));
#581=CARTESIAN_POINT('',(17.7303456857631,17.05,10.9201739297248));
#582=CARTESIAN_POINT('',(18.8046810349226,17.05,11.3882094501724));
#583=CARTESIAN_POINT('',(19.3400914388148,17.05,11.6262555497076));
#584=CARTESIAN_POINT('',(20.4077124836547,17.05,12.1091289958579));
#585=CARTESIAN_POINT('',(20.9399237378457,17.05,12.3539549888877));
#586=CARTESIAN_POINT('',(22.0016218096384,17.05,12.8494305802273));
#587=CARTESIAN_POINT('',(22.531108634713,17.05,13.1000801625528));
#588=CARTESIAN_POINT('',(24.049321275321,17.05,13.8275438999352));
#589=CARTESIAN_POINT('',(25.0350550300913,17.05,14.3106040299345));
#590=CARTESIAN_POINT('',(26.999950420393,17.05,15.2899855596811));
#591=CARTESIAN_POINT('',(27.9791116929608,17.05,15.7863076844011));
#592=CARTESIAN_POINT('',(29.9270073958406,17.05,16.7865810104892));
#593=CARTESIAN_POINT('',(30.8957695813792,17.05,17.2904782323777));
#594=CARTESIAN_POINT('',(32.3456864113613,17.05,18.0523103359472));
#595=CARTESIAN_POINT('',(32.828426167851,17.05,18.307237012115));
#596=CARTESIAN_POINT('',(33.7929469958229,17.05,18.818891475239));
#597=CARTESIAN_POINT('',(34.2747280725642,17.05,19.0756192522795));
#598=CARTESIAN_POINT('',(34.7560813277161,17.05,19.3331471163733));
#599=B_SPLINE_CURVE_WITH_KNOTS('',3,(#523,#524,#525,#526,#527,#528,#529,#530,#531,#532,#533,
#534,#535,#536,#537,#538,#539,#540,#541,#542,#543,#544,#545,#546,#547,#548,#549,#550,#551,#552,
#553,#554,#555,#556,#557,#558,#559,#560,#561,#562,#563,#564,#565,#566,#567,#568,#569,#570,#571,
#572,#573,#574,#575,#576,#577,#578,#579,#580,#581,#582,#583,#584,#585,#586,#587,#588,#589,#590,
#591,#592,#593,#594,#595,#596,#597,#598),.UNSPECIFIED.,.F.,.F.,(4,2,2,2,2,2,2,2,2,2,2,2,2,2,2,2,
2,2,2,2,2,2,2,2,2,2,2,2,2,2,2,2,2,2,2,2,2,4),(0.,2.66574670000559,5.33160393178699,
8.00119036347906,10.6707405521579,13.4831341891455,16.2956257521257,19.1067345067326,
20.5122208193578,21.9176833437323,23.5263827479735,25.1350192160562,26.7440043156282,
28.3529889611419,31.5061153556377,33.0823752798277,34.6586175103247,36.2648724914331,
37.8711103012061,39.4773048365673,41.0835371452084,42.7235772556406,44.3637899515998,
46.0047213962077,47.6456577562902,49.3993406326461,51.1531680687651,52.9076383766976,
54.6620634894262,56.4198308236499,58.1776068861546,59.9350345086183,61.6924573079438,
64.9855082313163,68.2787395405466,71.5546180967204,73.192365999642,74.830104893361),.UNSPECIFIED.);
#600=CARTESIAN_POINT('',(34.7560813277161,17.05,19.3331471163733));
#601=VERTEX_POINT('',#600);
#602=EDGE_CURVE('E1445',#520,#601,#599,.T.);
#603=ORIENTED_EDGE('',*,*,#602,.T.);
#604=CARTESIAN_POINT('',(34.7560813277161,17.05,19.3331471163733));
#605=CARTESIAN_POINT('',(34.9642160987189,17.0500388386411,19.4445654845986));
#606=CARTESIAN_POINT('',(35.1694190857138,17.0735554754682,19.5606672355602));
#607=CARTESIAN_POINT('',(35.5667554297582,17.164089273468,19.7972740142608));
#608=CARTESIAN_POINT('',(35.7589160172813,17.2310125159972,19.9177690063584));
#609=CARTESIAN_POINT('',(36.099678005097,17.3933837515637,20.1427185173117));
#610=CARTESIAN_POINT('',(36.2506750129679,17.4838625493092,20.2471778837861));
#611=CARTESIAN_POINT('',(36.5340722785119,17.6930027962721,20.4534650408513));
#612=CARTESIAN_POINT('',(36.6664589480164,17.8116846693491,20.5552908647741));
#613=CARTESIAN_POINT('',(36.9097263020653,18.0770520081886,20.7549142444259));
#614=CARTESIAN_POINT('',(37.0202464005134,18.224138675,20.8526261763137));
#615=CARTESIAN_POINT('',(37.1636021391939,18.4618665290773,20.9920574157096));
#616=CARTESIAN_POINT('',(37.2076243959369,18.5438882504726,21.0373125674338));
#617=CARTESIAN_POINT('',(37.2875839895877,18.7131623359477,21.1250514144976));
#618=CARTESIAN_POINT('',(37.3235269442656,18.8004110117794,21.1675370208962));
#619=CARTESIAN_POINT('',(37.3786448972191,18.9568600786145,21.2389212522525));
#620=CARTESIAN_POINT('',(37.3997621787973,19.0250543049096,21.2685416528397));
#621=CARTESIAN_POINT('',(37.4367840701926,19.1636345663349,21.3257302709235));
#622=CARTESIAN_POINT('',(37.4526913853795,19.234019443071,21.353299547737));
#623=CARTESIAN_POINT('',(37.465857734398,19.3053573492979,21.3797465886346));
#624=B_SPLINE_CURVE_WITH_KNOTS('',3,(#604,#605,#606,#607,#608,#609,#610,#611,#612,#613,#614,
#615,#616,#617,#618,#619,#620,#621,#622,#623),.UNSPECIFIED.,.F.,.F.,(4,2,2,2,2,2,2,2,2,4),(0.,
0.70656866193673,1.41161360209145,2.02301546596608,2.63486144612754,3.25608193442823,
3.56620934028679,3.87612043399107,4.10777053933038,4.33930016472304),.UNSPECIFIED.);
#625=EDGE_CURVE('E926',#601,#395,#624,.T.);
#626=ORIENTED_EDGE('',*,*,#625,.T.);
#627=ORIENTED_EDGE('',*,*,#396,.T.);
#628=CARTESIAN_POINT('',(37.465857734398,-19.305357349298,21.3797465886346));
#629=CARTESIAN_POINT('',(37.4506346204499,-19.222893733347,21.3491732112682));
#630=CARTESIAN_POINT('',(37.4317600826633,-19.1417288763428,21.3171129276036));
#631=CARTESIAN_POINT('',(37.3871473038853,-18.9825042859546,21.2503457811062));
#632=CARTESIAN_POINT('',(37.36141437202,-18.9044422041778,21.2156409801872));
#633=CARTESIAN_POINT('',(37.2748626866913,-18.6763284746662,21.1083733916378));
#634=CARTESIAN_POINT('',(37.2045125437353,-18.5314258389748,21.0323117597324));
#635=CARTESIAN_POINT('',(37.0423053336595,-18.2591559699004,20.8736588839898));
#636=CARTESIAN_POINT('',(36.9505105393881,-18.1317396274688,20.7910869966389));
#637=CARTESIAN_POINT('',(36.7485268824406,-17.8957384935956,20.6211835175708));
#638=CARTESIAN_POINT('',(36.6383094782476,-17.7871834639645,20.5338446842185));
#639=CARTESIAN_POINT('',(36.3900085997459,-17.5801946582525,20.346903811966));
#640=CARTESIAN_POINT('',(36.2502031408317,-17.4841040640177,20.2469929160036));
#641=CARTESIAN_POINT('',(35.9559631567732,-17.319233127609,20.0463793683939));
#642=CARTESIAN_POINT('',(35.8015348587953,-17.2504412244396,19.9456770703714));
#643=CARTESIAN_POINT('',(35.5007531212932,-17.1483578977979,19.7578042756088));
#644=CARTESIAN_POINT('',(35.3556140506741,-17.1118238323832,19.6704453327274));
#645=CARTESIAN_POINT('',(35.0595338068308,-17.0626556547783,19.4989251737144));
#646=CARTESIAN_POINT('',(34.9085924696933,-17.050022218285,19.4147640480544));
#647=CARTESIAN_POINT('',(34.7560813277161,-17.05,19.3331471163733));
#648=B_SPLINE_CURVE_WITH_KNOTS('',3,(#628,#629,#630,#631,#632,#633,#634,#635,#636,#637,#638,
#639,#640,#641,#642,#643,#644,#645,#646,#647),.UNSPECIFIED.,.F.,.F.,(4,2,2,2,2,2,2,2,2,4),(0.,
0.267554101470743,0.534901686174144,1.0666318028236,1.59683661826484,2.12787060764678,
2.71600119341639,3.3038824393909,3.82204375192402,4.34021971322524),.UNSPECIFIED.);
#649=CARTESIAN_POINT('',(34.7560813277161,-17.05,19.3331471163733));
#650=VERTEX_POINT('',#649);
#651=EDGE_CURVE('E460',#386,#650,#648,.T.);
#652=ORIENTED_EDGE('',*,*,#651,.T.);
#653=CARTESIAN_POINT('',(34.7560813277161,-17.05,19.3331471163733));
#654=CARTESIAN_POINT('',(33.9725683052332,-17.05,18.9140040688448));
#655=CARTESIAN_POINT('',(33.187944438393,-17.05,18.4969215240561));
#656=CARTESIAN_POINT('',(31.6159567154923,-17.05,17.6678754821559));
#657=CARTESIAN_POINT('',(30.8285927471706,-17.05,17.2559121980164));
#658=CARTESIAN_POINT('',(29.2495677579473,-17.05,16.4375656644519));
#659=CARTESIAN_POINT('',(28.4579022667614,-17.05,16.031191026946));
#660=CARTESIAN_POINT('',(26.8707444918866,-17.05,15.2260017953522));
#661=CARTESIAN_POINT('',(26.0752522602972,-17.05,14.827187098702));
#662=CARTESIAN_POINT('',(24.4369579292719,-17.05,14.0177947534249));
#663=CARTESIAN_POINT('',(23.5939019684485,-17.05,13.6077295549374));
#664=CARTESIAN_POINT('',(21.9014905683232,-17.05,12.8007036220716));
#665=CARTESIAN_POINT('',(21.052134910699,-17.05,12.4037433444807));
#666=CARTESIAN_POINT('',(19.3461264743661,-17.05,11.626846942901));
#667=CARTESIAN_POINT('',(18.4894774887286,-17.05,11.2469025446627));
#668=CARTESIAN_POINT('',(17.1974661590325,-17.05,10.6934878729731));
#669=CARTESIAN_POINT('',(16.7656332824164,-17.05,10.5117708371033));
#670=CARTESIAN_POINT('',(15.8993625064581,-17.05,10.1546646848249));
#671=CARTESIAN_POINT('',(15.4649246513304,-17.05,9.97927546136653));
#672=CARTESIAN_POINT('',(14.5301471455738,-17.05,9.61092120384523));
#673=CARTESIAN_POINT('',(14.0293621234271,-17.05,9.41908211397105));
#674=CARTESIAN_POINT('',(13.0236598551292,-17.05,9.04659617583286));
#675=CARTESIAN_POINT('',(12.5187427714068,-17.05,8.86594888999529));
#676=CARTESIAN_POINT('',(11.5042481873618,-17.05,8.51776826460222));
#677=CARTESIAN_POINT('',(10.9946697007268,-17.05,8.35023777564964));
#678=CARTESIAN_POINT('',(9.97072277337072,-17.05,8.03064595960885));
#679=CARTESIAN_POINT('',(9.45635433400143,-17.05,7.87858462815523));
#680=CARTESIAN_POINT('',(7.92620850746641,-17.05,7.45517806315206));
#681=CARTESIAN_POINT('',(6.90297443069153,-17.05,7.20940813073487));
#682=CARTESIAN_POINT('',(5.35516076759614,-17.05,6.9090979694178));
#683=CARTESIAN_POINT('',(4.83711291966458,-17.05,6.82039061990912));
#684=CARTESIAN_POINT('',(3.79725745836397,-17.05,6.66828978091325));
#685=CARTESIAN_POINT('',(3.27544988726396,-17.05,6.60489600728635));
#686=CARTESIAN_POINT('',(2.21924330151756,-17.05,6.50459293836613));
#687=CARTESIAN_POINT('',(1.68479371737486,-17.05,6.46821090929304));
#688=CARTESIAN_POINT('',(0.614687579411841,-17.05,6.42530779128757));
#689=CARTESIAN_POINT('',(0.0790310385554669,-17.05,6.41878638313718));
#690=CARTESIAN_POINT('',(-0.991781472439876,-17.05,6.43586040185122));
#691=CARTESIAN_POINT('',(-1.52693745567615,-17.05,6.4594550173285));
#692=CARTESIAN_POINT('',(-2.59514834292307,-17.05,6.53584590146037));
#693=CARTESIAN_POINT('',(-3.12820319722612,-17.05,6.5886428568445));
#694=CARTESIAN_POINT('',(-4.20204910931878,-17.05,6.722932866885));
#695=CARTESIAN_POINT('',(-4.74276684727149,-17.05,6.80500652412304));
#696=CARTESIAN_POINT('',(-5.8196774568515,-17.05,6.99488444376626));
#697=CARTESIAN_POINT('',(-6.35586984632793,-17.05,7.10269141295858));
#698=CARTESIAN_POINT('',(-7.42338587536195,-17.05,7.34102353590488));
#699=CARTESIAN_POINT('',(-7.95470727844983,-17.05,7.47155862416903));
#700=CARTESIAN_POINT('',(-9.01210309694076,-17.05,7.75225748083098));
#701=CARTESIAN_POINT('',(-9.53817749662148,-17.05,7.90242130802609));
#702=CARTESIAN_POINT('',(-10.621187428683,-17.05,8.23042811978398));
#703=CARTESIAN_POINT('',(-11.1777598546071,-17.05,8.40946399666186));
#704=CARTESIAN_POINT('',(-12.2854805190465,-17.05,8.78365072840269));
#705=CARTESIAN_POINT('',(-12.8366283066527,-17.05,8.97880291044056));
#706=CARTESIAN_POINT('',(-13.9341401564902,-17.05,9.38267214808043));
#707=CARTESIAN_POINT('',(-14.4805023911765,-17.05,9.59139414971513));
#708=CARTESIAN_POINT('',(-15.5687390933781,-17.05,10.0201486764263));
#709=CARTESIAN_POINT('',(-16.1106136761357,-17.05,10.2401809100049));
#710=CARTESIAN_POINT('',(-17.1914207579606,-17.05,10.6901844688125));
#711=CARTESIAN_POINT('',(-17.7303456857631,-17.05,10.9201739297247));
#712=CARTESIAN_POINT('',(-18.8046810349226,-17.05,11.3882094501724));
#713=CARTESIAN_POINT('',(-19.3400914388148,-17.05,11.6262555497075));
#714=CARTESIAN_POINT('',(-20.4077124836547,-17.05,12.1091289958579));
#715=CARTESIAN_POINT('',(-20.9399237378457,-17.05,12.3539549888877));
#716=CARTESIAN_POINT('',(-22.0016218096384,-17.05,12.8494305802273));
#717=CARTESIAN_POINT('',(-22.531108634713,-17.05,13.1000801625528));
#718=CARTESIAN_POINT('',(-24.049321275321,-17.05,13.8275438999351));
#719=CARTESIAN_POINT('',(-25.0350550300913,-17.05,14.3106040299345));
#720=CARTESIAN_POINT('',(-26.999950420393,-17.05,15.289985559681));
#721=CARTESIAN_POINT('',(-27.9791116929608,-17.05,15.786307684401));
#722=CARTESIAN_POINT('',(-29.9270073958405,-17.05,16.7865810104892));
#723=CARTESIAN_POINT('',(-30.8957695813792,-17.05,17.2904782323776));
#724=CARTESIAN_POINT('',(-32.3456864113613,-17.05,18.0523103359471));
#725=CARTESIAN_POINT('',(-32.828426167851,-17.05,18.307237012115));
#726=CARTESIAN_POINT('',(-33.7929469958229,-17.05,18.8188914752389));
#727=CARTESIAN_POINT('',(-34.2747280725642,-17.05,19.0756192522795));
#728=CARTESIAN_POINT('',(-34.7560813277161,-17.05,19.3331471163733));
#729=B_SPLINE_CURVE_WITH_KNOTS('',3,(#653,#654,#655,#656,#657,#658,#659,#660,#661,#662,#663,
#664,#665,#666,#667,#668,#669,#670,#671,#672,#673,#674,#675,#676,#677,#678,#679,#680,#681,#682,
#683,#684,#685,#686,#687,#688,#689,#690,#691,#692,#693,#694,#695,#696,#697,#698,#699,#700,#701,
#702,#703,#704,#705,#706,#707,#708,#709,#710,#711,#712,#713,#714,#715,#716,#717,#718,#719,#720,
#721,#722,#723,#724,#725,#726,#727,#728),.UNSPECIFIED.,.F.,.F.,(4,2,2,2,2,2,2,2,2,2,2,2,2,2,2,2,
2,2,2,2,2,2,2,2,2,2,2,2,2,2,2,2,2,2,2,2,2,4),(0.,2.66574670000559,5.331603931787,
8.00119036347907,10.6707405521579,13.4831341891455,16.2956257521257,19.1067345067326,
20.5122208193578,21.9176833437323,23.5263827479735,25.1350192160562,26.7440043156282,
28.352988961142,31.5061153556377,33.0823752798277,34.6586175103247,36.2648724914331,
37.8711103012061,39.4773048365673,41.0835371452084,42.7235772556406,44.3637899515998,
46.0047213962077,47.6456577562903,49.3993406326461,51.1531680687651,52.9076383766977,
54.6620634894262,56.41983082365,58.1776068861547,59.9350345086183,61.6924573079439,
64.9855082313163,68.2787395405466,71.5546180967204,73.192365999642,74.830104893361),.UNSPECIFIED.);
#730=EDGE_CURVE('E925',#650,#494,#729,.T.);
#731=ORIENTED_EDGE('',*,*,#730,.T.);
#732=EDGE_LOOP('',(#496,#497,#522,#603,#626,#627,#652,#731));
#733=FACE_BOUND('',#732,.T.);
#734=ADVANCED_FACE('F473',(#471,#733),#468,.T.);
#735=CARTESIAN_POINT('',(0.,0.,33.770311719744));
#736=DIRECTION('',(0.,0.,-1.));
#737=DIRECTION('',(0.,1.,0.));
#738=AXIS2_PLACEMENT_3D('',#735,#736,#737);
#739=TOROIDAL_SURFACE('',#738,40.,21.9999999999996);
#740=CARTESIAN_POINT('',(0.,0.,39.4643307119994));
#741=DIRECTION('',(0.,0.,-1.));
#742=DIRECTION('',(0.,1.,0.));
#743=AXIS2_PLACEMENT_3D('',#740,#741,#742);
#744=CIRCLE('',#743,61.2503681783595);
#745=CARTESIAN_POINT('',(0.,61.2503681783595,39.4643307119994));
#746=VERTEX_POINT('',#745);
#747=EDGE_CURVE('E915',#746,#746,#744,.T.);
#748=ORIENTED_EDGE('',*,*,#747,.T.);
#749=EDGE_LOOP('',(#748));
#750=FACE_BOUND('',#749,.T.);
#751=ORIENTED_EDGE('',*,*,#274,.F.);
#752=EDGE_LOOP('',(#751));
#753=FACE_BOUND('',#752,.T.);
#754=ADVANCED_FACE('F418',(#750,#753),#739,.T.);
#755=CARTESIAN_POINT('',(0.,0.,0.));
#756=DIRECTION('',(0.,0.,-1.));
#757=DIRECTION('',(0.,1.,0.));
#758=AXIS2_PLACEMENT_3D('',#755,#756,#757);
#759=CYLINDRICAL_SURFACE('',#758,42.7586206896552);
#760=DIRECTION('',(0.,0.,-1.));
#761=VECTOR('',#760,1.);
#762=CARTESIAN_POINT('',(-37.1502056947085,21.1698337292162,0.));
#763=LINE('',#762,#761);
#764=CARTESIAN_POINT('',(-37.1502056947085,21.1698337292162,28.6098003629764));
#765=VERTEX_POINT('',#764);
#766=EDGE_CURVE('E397',#293,#765,#763,.F.);
#767=ORIENTED_EDGE('',*,*,#766,.F.);
#768=ORIENTED_EDGE('',*,*,#296,.T.);
#769=DIRECTION('',(0.,0.,-1.));
#770=VECTOR('',#769,1.);
#771=CARTESIAN_POINT('',(37.1502057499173,21.1698336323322,0.));
#772=LINE('',#771,#770);
#773=CARTESIAN_POINT('',(37.1502057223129,21.1698336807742,28.6098003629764));
#774=VERTEX_POINT('',#773);
#775=EDGE_CURVE('E967',#295,#774,#772,.F.);
#776=ORIENTED_EDGE('',*,*,#775,.T.);
#777=CARTESIAN_POINT('',(0.,0.,28.6098003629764));
#778=DIRECTION('',(0.,0.,-1.));
#779=DIRECTION('',(0.,1.,0.));
#780=AXIS2_PLACEMENT_3D('',#777,#778,#779);
#781=CIRCLE('',#780,42.7586206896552);
#782=EDGE_CURVE('E919',#765,#774,#781,.T.);
#783=ORIENTED_EDGE('',*,*,#782,.F.);
#784=EDGE_LOOP('',(#767,#768,#776,#783));
#785=FACE_BOUND('',#784,.T.);
#786=ADVANCED_FACE('F369',(#785),#759,.F.);
#787=CARTESIAN_POINT('',(-34.7560813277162,19.8055555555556,0.));
#788=DIRECTION('',(0.,0.,-1.));
#789=DIRECTION('',(0.,1.,0.));
#790=AXIS2_PLACEMENT_3D('',#787,#788,#789);
#791=CYLINDRICAL_SURFACE('',#790,2.75555555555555);
#792=DIRECTION('',(0.,0.,-1.));
#793=VECTOR('',#792,1.);
#794=CARTESIAN_POINT('',(-34.7560813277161,17.05,0.));
#795=LINE('',#794,#793);
#796=CARTESIAN_POINT('',(-34.7560813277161,17.05,28.0740326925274));
#797=VERTEX_POINT('',#796);
#798=EDGE_CURVE('E398',#520,#797,#795,.F.);
#799=ORIENTED_EDGE('',*,*,#798,.F.);
#800=ORIENTED_EDGE('',*,*,#521,.F.);
#801=ORIENTED_EDGE('',*,*,#319,.T.);
#802=ORIENTED_EDGE('',*,*,#766,.T.);
#803=CARTESIAN_POINT('',(-34.7560813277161,17.05,28.0740326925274));
#804=CARTESIAN_POINT('',(-34.8342764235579,17.0499928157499,28.0833292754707));
#805=CARTESIAN_POINT('',(-34.912443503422,17.0533284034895,28.0928232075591));
#806=CARTESIAN_POINT('',(-35.0681681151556,17.0666169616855,28.1121307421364));
#807=CARTESIAN_POINT('',(-35.1457256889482,17.076569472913,28.1219443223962));
#808=CARTESIAN_POINT('',(-35.2996318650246,17.1030139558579,28.1418100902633));
#809=CARTESIAN_POINT('',(-35.3759813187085,17.1195010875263,28.151862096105));
#810=CARTESIAN_POINT('',(-35.5269663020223,17.1588749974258,28.1721329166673));
#811=CARTESIAN_POINT('',(-35.601601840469,17.181761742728,28.1823517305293));
#812=CARTESIAN_POINT('',(-35.8222026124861,17.2598233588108,28.2131553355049));
#813=CARTESIAN_POINT('',(-35.9649431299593,17.3244136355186,28.2338977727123));
#814=CARTESIAN_POINT('',(-36.2373723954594,17.4767678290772,28.2751571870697));
#815=CARTESIAN_POINT('',(-36.3670632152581,17.5645280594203,28.2956741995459));
#816=CARTESIAN_POINT('',(-36.610001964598,17.7609330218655,28.3359641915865));
#817=CARTESIAN_POINT('',(-36.7232266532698,17.8696067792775,28.355736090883));
#818=CARTESIAN_POINT('',(-36.9297252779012,18.1047186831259,28.393972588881));
#819=CARTESIAN_POINT('',(-37.0229964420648,18.2311592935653,28.4124370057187));
#820=CARTESIAN_POINT('',(-37.1865401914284,18.4977610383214,28.4475083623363));
#821=CARTESIAN_POINT('',(-37.2568904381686,18.6378737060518,28.4641214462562));
#822=CARTESIAN_POINT('',(-37.3728975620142,18.9281808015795,28.4951291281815));
#823=CARTESIAN_POINT('',(-37.4185589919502,19.0783733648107,28.5095241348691));
#824=CARTESIAN_POINT('',(-37.4835428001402,19.3834322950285,28.5356334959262));
#825=CARTESIAN_POINT('',(-37.5030533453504,19.5382569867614,28.5473664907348));
#826=CARTESIAN_POINT('',(-37.5156824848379,19.8492528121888,28.5679923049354));
#827=CARTESIAN_POINT('',(-37.5087888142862,20.0054245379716,28.5768838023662));
#828=CARTESIAN_POINT('',(-37.4688512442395,20.3134317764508,28.5915441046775));
#829=CARTESIAN_POINT('',(-37.435985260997,20.465289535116,28.5973337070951));
#830=CARTESIAN_POINT('',(-37.345238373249,20.7611674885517,28.6057269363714));
#831=CARTESIAN_POINT('',(-37.2874126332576,20.9052041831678,28.6083375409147));
#832=CARTESIAN_POINT('',(-37.1965257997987,21.0860394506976,28.6096464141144));
#833=CARTESIAN_POINT('',(-37.1739067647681,21.1282584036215,28.6098012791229));
#834=CARTESIAN_POINT('',(-37.1502056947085,21.1698337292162,28.6098003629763));
#835=B_SPLINE_CURVE_WITH_KNOTS('',3,(#803,#804,#805,#806,#807,#808,#809,#810,#811,#812,#813,
#814,#815,#816,#817,#818,#819,#820,#821,#822,#823,#824,#825,#826,#827,#828,#829,#830,#831,#832,
#833,#834),.UNSPECIFIED.,.F.,.F.,(4,2,2,2,2,2,2,2,2,2,2,2,2,2,2,4),(0.,0.23615869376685,
0.47230099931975,0.708268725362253,0.94423523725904,1.41592240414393,1.88753456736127,
2.35980605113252,2.83214309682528,3.30286269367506,3.77349545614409,4.24072329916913,
4.70816819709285,5.17243846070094,5.63568783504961,5.77930499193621),.UNSPECIFIED.);
#836=EDGE_CURVE('E389',#797,#765,#835,.T.);
#837=ORIENTED_EDGE('',*,*,#836,.F.);
#838=EDGE_LOOP('',(#799,#800,#801,#802,#837));
#839=FACE_BOUND('',#838,.T.);
#840=ADVANCED_FACE('F364',(#839),#791,.F.);
#841=CARTESIAN_POINT('',(34.7560813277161,17.05,0.));
#842=DIRECTION('',(0.,-1.,0.));
#843=DIRECTION('',(1.,0.,0.));
#844=AXIS2_PLACEMENT_3D('',#841,#842,#843);
#845=PLANE('',#844);
#846=DIRECTION('',(0.,0.,-1.));
#847=VECTOR('',#846,1.);
#848=CARTESIAN_POINT('',(34.7560813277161,17.05,0.));
#849=LINE('',#848,#847);
#850=CARTESIAN_POINT('',(34.7560813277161,17.05,28.0740326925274));
#851=VERTEX_POINT('',#850);
#852=EDGE_CURVE('E921',#851,#601,#849,.T.);
#853=ORIENTED_EDGE('',*,*,#852,.T.);
#854=ORIENTED_EDGE('',*,*,#602,.F.);
#855=ORIENTED_EDGE('',*,*,#798,.T.);
#856=CARTESIAN_POINT('',(34.7560813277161,17.05,28.0740326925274));
#857=CARTESIAN_POINT('',(33.9484792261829,17.05,27.9780255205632));
#858=CARTESIAN_POINT('',(33.1408028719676,17.05,27.8826381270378));
#859=CARTESIAN_POINT('',(31.5252691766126,17.05,27.6933900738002));
#860=CARTESIAN_POINT('',(30.7174118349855,17.05,27.5995294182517));
#861=CARTESIAN_POINT('',(29.1014758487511,17.05,27.4136211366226));
#862=CARTESIAN_POINT('',(28.293397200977,17.05,27.3215735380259));
#863=CARTESIAN_POINT('',(26.6769930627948,17.05,27.1396725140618));
#864=CARTESIAN_POINT('',(25.8686675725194,17.05,27.0498190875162));
#865=CARTESIAN_POINT('',(24.2492301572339,17.05,26.8725071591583));
#866=CARTESIAN_POINT('',(23.4381173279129,17.05,26.7850568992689));
#867=CARTESIAN_POINT('',(21.8155437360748,17.05,26.6134485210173));
#868=CARTESIAN_POINT('',(21.004082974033,17.05,26.5292903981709));
#869=CARTESIAN_POINT('',(19.3807184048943,17.05,26.3650343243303));
#870=CARTESIAN_POINT('',(18.5688145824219,17.05,26.284936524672));
#871=CARTESIAN_POINT('',(16.9445239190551,17.05,26.1297802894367));
#872=CARTESIAN_POINT('',(16.1321370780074,17.05,26.0547218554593));
#873=CARTESIAN_POINT('',(14.513230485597,17.05,25.9114359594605));
#874=CARTESIAN_POINT('',(13.706715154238,17.05,25.8431591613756));
#875=CARTESIAN_POINT('',(12.0930824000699,17.05,25.7142262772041));
#876=CARTESIAN_POINT('',(11.2859649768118,17.05,25.653570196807));
#877=CARTESIAN_POINT('',(8.86368542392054,17.05,25.4856225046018));
#878=CARTESIAN_POINT('',(7.24747165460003,17.05,25.3923399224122));
#879=CARTESIAN_POINT('',(4.82271159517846,17.05,25.291651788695));
#880=CARTESIAN_POINT('',(4.01496948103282,17.05,25.2646337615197));
#881=CARTESIAN_POINT('',(2.39912321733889,17.05,25.2250832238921));
#882=CARTESIAN_POINT('',(1.59101906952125,17.05,25.2125506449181));
#883=CARTESIAN_POINT('',(-0.025262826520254,17.05,25.2027335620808));
#884=CARTESIAN_POINT('',(-0.833440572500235,17.05,25.2054486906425));
#885=CARTESIAN_POINT('',(-2.44960270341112,17.05,25.2259583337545));
#886=CARTESIAN_POINT('',(-3.25758708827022,17.05,25.2437528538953));
#887=CARTESIAN_POINT('',(-4.70498507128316,17.05,25.2882021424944));
#888=CARTESIAN_POINT('',(-5.34448148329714,17.05,25.3122418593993));
#889=CARTESIAN_POINT('',(-6.62312643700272,17.05,25.3683164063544));
#890=CARTESIAN_POINT('',(-7.26227497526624,17.05,25.4003513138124));
#891=CARTESIAN_POINT('',(-9.17914658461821,17.05,25.5070776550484));
#892=CARTESIAN_POINT('',(-10.4562798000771,17.05,25.5923901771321));
#893=CARTESIAN_POINT('',(-13.0104654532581,17.05,25.7841206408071));
#894=CARTESIAN_POINT('',(-14.2875159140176,17.05,25.8905640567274));
#895=CARTESIAN_POINT('',(-16.8402362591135,17.05,26.1184782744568));
#896=CARTESIAN_POINT('',(-18.1159061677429,17.05,26.239948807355));
#897=CARTESIAN_POINT('',(-20.6743481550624,17.05,26.4943929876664));
#898=CARTESIAN_POINT('',(-21.9571133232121,17.05,26.6274354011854));
#899=CARTESIAN_POINT('',(-24.5218178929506,17.05,26.9012825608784));
#900=CARTESIAN_POINT('',(-25.8037572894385,17.05,27.042087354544));
#901=CARTESIAN_POINT('',(-28.3643829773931,17.05,27.3290633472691));
#902=CARTESIAN_POINT('',(-29.6430705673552,17.05,27.4752230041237));
#903=CARTESIAN_POINT('',(-31.5607214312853,17.05,27.6976108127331));
#904=CARTESIAN_POINT('',(-32.1998681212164,17.05,27.7722639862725));
#905=CARTESIAN_POINT('',(-33.4780526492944,17.05,27.9224905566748));
#906=CARTESIAN_POINT('',(-34.1170904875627,17.05,27.998063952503));
#907=CARTESIAN_POINT('',(-34.7560813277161,17.05,28.0740326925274));
#908=B_SPLINE_CURVE_WITH_KNOTS('',3,(#856,#857,#858,#859,#860,#861,#862,#863,#864,#865,#866,
#867,#868,#869,#870,#871,#872,#873,#874,#875,#876,#877,#878,#879,#880,#881,#882,#883,#884,#885,
#886,#887,#888,#889,#890,#891,#892,#893,#894,#895,#896,#897,#898,#899,#900,#901,#902,#903,#904,
#905,#906,#907),.UNSPECIFIED.,.F.,.F.,(4,2,2,2,2,2,2,2,2,2,2,2,2,2,2,2,2,2,2,2,2,2,2,2,2,4),(0.,
2.4398667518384,4.87974015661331,7.31965051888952,9.75955957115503,12.2069944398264,
14.6544259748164,17.1019486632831,19.5494721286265,21.9776359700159,24.4058016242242,
29.2617583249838,31.6862315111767,34.1106932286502,36.5350965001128,38.959500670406,
40.879292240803,42.7991023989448,46.6387702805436,50.4830954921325,54.327351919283,
58.1962585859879,62.0651889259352,65.9262209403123,67.8566955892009,69.7871680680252),.UNSPECIFIED.);
#909=EDGE_CURVE('E439',#851,#797,#908,.T.);
#910=ORIENTED_EDGE('',*,*,#909,.F.);
#911=EDGE_LOOP('',(#853,#854,#855,#910));
#912=FACE_BOUND('',#911,.T.);
#913=ADVANCED_FACE('F368',(#912),#845,.F.);
#914=CARTESIAN_POINT('',(34.7560813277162,19.8055555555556,0.));
#915=DIRECTION('',(0.,0.,-1.));
#916=DIRECTION('',(0.,1.,0.));
#917=AXIS2_PLACEMENT_3D('',#914,#915,#916);
#918=CYLINDRICAL_SURFACE('',#917,2.75555555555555);
#919=ORIENTED_EDGE('',*,*,#775,.F.);
#920=ORIENTED_EDGE('',*,*,#421,.T.);
#921=ORIENTED_EDGE('',*,*,#625,.F.);
#922=ORIENTED_EDGE('',*,*,#852,.F.);
#923=CARTESIAN_POINT('',(37.1502057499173,21.1698336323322,28.6098003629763));
#924=CARTESIAN_POINT('',(37.1883688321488,21.1028781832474,28.6098011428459));
#925=CARTESIAN_POINT('',(37.223707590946,21.0343175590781,28.6093997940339));
#926=CARTESIAN_POINT('',(37.2885175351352,20.894490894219,28.6077989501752));
#927=CARTESIAN_POINT('',(37.3179890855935,20.8232250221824,28.6065995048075));
#928=CARTESIAN_POINT('',(37.3708263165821,20.6785505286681,28.6034100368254));
#929=CARTESIAN_POINT('',(37.3941975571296,20.6051439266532,28.601420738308));
#930=CARTESIAN_POINT('',(37.4347106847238,20.4566780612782,28.5966657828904));
#931=CARTESIAN_POINT('',(37.451852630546,20.3816188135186,28.5939001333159));
#932=CARTESIAN_POINT('',(37.4937457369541,20.1546855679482,28.5844579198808));
#933=CARTESIAN_POINT('',(37.5089901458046,20.000984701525,28.5766345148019));
#934=CARTESIAN_POINT('',(37.5136533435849,19.6934729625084,28.5581350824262));
#935=CARTESIAN_POINT('',(37.5030757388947,19.5396621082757,28.5474594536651));
#936=CARTESIAN_POINT('',(37.4564492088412,19.2356321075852,28.5234764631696));
#937=CARTESIAN_POINT('',(37.4203182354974,19.0854261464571,28.5101607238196));
#938=CARTESIAN_POINT('',(37.3235993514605,18.7933206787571,28.4812492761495));
#939=CARTESIAN_POINT('',(37.2630068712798,18.6514227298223,28.4656531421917));
#940=CARTESIAN_POINT('',(37.1186316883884,18.3788839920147,28.4324524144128));
#941=CARTESIAN_POINT('',(37.0346844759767,18.2483320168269,28.4148341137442));
#942=CARTESIAN_POINT('',(36.8462416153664,18.003277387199,28.3781353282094));
#943=CARTESIAN_POINT('',(36.7417480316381,17.8887731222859,28.3590549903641));
#944=CARTESIAN_POINT('',(36.5143467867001,17.6781670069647,28.3197834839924));
#945=CARTESIAN_POINT('',(36.3913101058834,17.5822057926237,28.2995852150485));
#946=CARTESIAN_POINT('',(36.1308129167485,17.4123606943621,28.2587412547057));
#947=CARTESIAN_POINT('',(35.993345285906,17.338487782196,28.238095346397));
#948=CARTESIAN_POINT('',(35.7071707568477,17.2146142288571,28.1968337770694));
#949=CARTESIAN_POINT('',(35.5584070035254,17.1647450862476,28.1762188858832));
#950=CARTESIAN_POINT('',(35.2546544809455,17.090994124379,28.1357549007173));
#951=CARTESIAN_POINT('',(35.0996787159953,17.0670606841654,28.1159043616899));
#952=CARTESIAN_POINT('',(34.9126769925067,17.0542732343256,28.0929069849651));
#953=CARTESIAN_POINT('',(34.8813632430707,17.0526702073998,28.0890879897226));
#954=CARTESIAN_POINT('',(34.8187312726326,17.0505350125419,28.0815134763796));
#955=CARTESIAN_POINT('',(34.787413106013,17.0500015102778,28.0777578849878));
#956=CARTESIAN_POINT('',(34.7560813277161,17.05,28.0740326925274));
#957=B_SPLINE_CURVE_WITH_KNOTS('',3,(#923,#924,#925,#926,#927,#928,#929,#930,#931,#932,#933,
#934,#935,#936,#937,#938,#939,#940,#941,#942,#943,#944,#945,#946,#947,#948,#949,#950,#951,#952,
#953,#954,#955,#956),.UNSPECIFIED.,.F.,.F.,(4,2,2,2,2,2,2,2,2,2,2,2,2,2,2,2,4),(0.,
0.231127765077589,0.46224114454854,0.693143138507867,0.92404295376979,1.38561756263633,
1.84712771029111,2.31012646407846,2.77321174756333,3.23964538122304,3.70603217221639,
4.175828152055,4.64585710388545,5.11843248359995,5.59006553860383,5.68481681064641,
5.77944979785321),.UNSPECIFIED.);
#958=EDGE_CURVE('E399',#774,#851,#957,.T.);
#959=ORIENTED_EDGE('',*,*,#958,.F.);
#960=EDGE_LOOP('',(#919,#920,#921,#922,#959));
#961=FACE_BOUND('',#960,.T.);
#962=ADVANCED_FACE('F1302',(#961),#918,.F.);
#963=CARTESIAN_POINT('',(-7.75,0.,25.));
#964=DIRECTION('',(0.,0.,1.));
#965=DIRECTION('',(-1.,0.,0.));
#966=AXIS2_PLACEMENT_3D('',#963,#964,#965);
#967=PLANE('',#966);
#968=CARTESIAN_POINT('',(0.,0.,25.));
#969=DIRECTION('',(0.,0.,1.));
#970=DIRECTION('',(-1.,0.,0.));
#971=AXIS2_PLACEMENT_3D('',#968,#969,#970);
#972=CIRCLE('',#971,15.5);
#973=CARTESIAN_POINT('',(-15.5,0.,25.));
#974=VERTEX_POINT('',#973);
#975=EDGE_CURVE('E1523',#974,#974,#972,.T.);
#976=ORIENTED_EDGE('',*,*,#975,.T.);
#977=EDGE_LOOP('',(#976));
#978=FACE_BOUND('',#977,.T.);
#979=ADVANCED_FACE('F597',(#978),#967,.T.);
#980=CARTESIAN_POINT('',(-34.7560813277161,-17.05,0.));
#981=DIRECTION('',(0.,1.,0.));
#982=DIRECTION('',(-1.,0.,0.));
#983=AXIS2_PLACEMENT_3D('',#980,#981,#982);
#984=PLANE('',#983);
#985=DIRECTION('',(0.,0.,-1.));
#986=VECTOR('',#985,1.);
#987=CARTESIAN_POINT('',(34.7560813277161,-17.05,0.));
#988=LINE('',#987,#986);
#989=CARTESIAN_POINT('',(34.7560813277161,-17.05,28.0740326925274));
#990=VERTEX_POINT('',#989);
#991=EDGE_CURVE('E457',#650,#990,#988,.F.);
#992=ORIENTED_EDGE('',*,*,#991,.T.);
#993=CARTESIAN_POINT('',(34.7560813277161,-17.05,28.0740326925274));
#994=CARTESIAN_POINT('',(33.9484792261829,-17.05,27.9780255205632));
#995=CARTESIAN_POINT('',(33.1408028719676,-17.05,27.8826381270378));
#996=CARTESIAN_POINT('',(31.5252691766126,-17.05,27.6933900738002));
#997=CARTESIAN_POINT('',(30.7174118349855,-17.05,27.5995294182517));
#998=CARTESIAN_POINT('',(29.1014758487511,-17.05,27.4136211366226));
#999=CARTESIAN_POINT('',(28.293397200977,-17.05,27.3215735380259));
#1000=CARTESIAN_POINT('',(26.6769930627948,-17.05,27.1396725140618));
#1001=CARTESIAN_POINT('',(25.8686675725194,-17.05,27.0498190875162));
#1002=CARTESIAN_POINT('',(24.2492301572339,-17.05,26.8725071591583));
#1003=CARTESIAN_POINT('',(23.4381173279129,-17.05,26.7850568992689));
#1004=CARTESIAN_POINT('',(21.8155437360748,-17.05,26.6134485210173));
#1005=CARTESIAN_POINT('',(21.004082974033,-17.05,26.5292903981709));
#1006=CARTESIAN_POINT('',(19.3807184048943,-17.05,26.3650343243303));
#1007=CARTESIAN_POINT('',(18.5688145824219,-17.05,26.284936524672));
#1008=CARTESIAN_POINT('',(16.9445239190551,-17.05,26.1297802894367));
#1009=CARTESIAN_POINT('',(16.1321370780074,-17.05,26.0547218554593));
#1010=CARTESIAN_POINT('',(14.513230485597,-17.05,25.9114359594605));
#1011=CARTESIAN_POINT('',(13.706715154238,-17.05,25.8431591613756));
#1012=CARTESIAN_POINT('',(12.0930824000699,-17.05,25.7142262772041));
#1013=CARTESIAN_POINT('',(11.2859649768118,-17.05,25.653570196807));
#1014=CARTESIAN_POINT('',(8.86368542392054,-17.05,25.4856225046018));
#1015=CARTESIAN_POINT('',(7.24747165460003,-17.05,25.3923399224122));
#1016=CARTESIAN_POINT('',(4.82271159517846,-17.05,25.291651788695));
#1017=CARTESIAN_POINT('',(4.01496948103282,-17.05,25.2646337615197));
#1018=CARTESIAN_POINT('',(2.39912321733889,-17.05,25.2250832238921));
#1019=CARTESIAN_POINT('',(1.59101906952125,-17.05,25.2125506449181));
#1020=CARTESIAN_POINT('',(-0.025262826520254,-17.05,25.2027335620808));
#1021=CARTESIAN_POINT('',(-0.833440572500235,-17.05,25.2054486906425));
#1022=CARTESIAN_POINT('',(-2.44960270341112,-17.05,25.2259583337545));
#1023=CARTESIAN_POINT('',(-3.25758708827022,-17.05,25.2437528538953));
#1024=CARTESIAN_POINT('',(-4.70498507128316,-17.05,25.2882021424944));
#1025=CARTESIAN_POINT('',(-5.34448148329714,-17.05,25.3122418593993));
#1026=CARTESIAN_POINT('',(-6.62312643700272,-17.05,25.3683164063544));
#1027=CARTESIAN_POINT('',(-7.26227497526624,-17.05,25.4003513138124));
#1028=CARTESIAN_POINT('',(-9.17914658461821,-17.05,25.5070776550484));
#1029=CARTESIAN_POINT('',(-10.4562798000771,-17.05,25.5923901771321));
#1030=CARTESIAN_POINT('',(-13.0104654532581,-17.05,25.7841206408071));
#1031=CARTESIAN_POINT('',(-14.2875159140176,-17.05,25.8905640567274));
#1032=CARTESIAN_POINT('',(-16.8402362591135,-17.05,26.1184782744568));
#1033=CARTESIAN_POINT('',(-18.1159061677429,-17.05,26.239948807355));
#1034=CARTESIAN_POINT('',(-20.6743481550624,-17.05,26.4943929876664));
#1035=CARTESIAN_POINT('',(-21.9571133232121,-17.05,26.6274354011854));
#1036=CARTESIAN_POINT('',(-24.5218178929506,-17.05,26.9012825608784));
#1037=CARTESIAN_POINT('',(-25.8037572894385,-17.05,27.042087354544));
#1038=CARTESIAN_POINT('',(-28.3643829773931,-17.05,27.3290633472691));
#1039=CARTESIAN_POINT('',(-29.6430705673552,-17.05,27.4752230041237));
#1040=CARTESIAN_POINT('',(-31.5607214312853,-17.05,27.6976108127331));
#1041=CARTESIAN_POINT('',(-32.1998681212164,-17.05,27.7722639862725));
#1042=CARTESIAN_POINT('',(-33.4780526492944,-17.05,27.9224905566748));
#1043=CARTESIAN_POINT('',(-34.1170904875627,-17.05,27.998063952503));
#1044=CARTESIAN_POINT('',(-34.7560813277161,-17.05,28.0740326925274));
#1045=B_SPLINE_CURVE_WITH_KNOTS('',3,(#993,#994,#995,#996,#997,#998,#999,#1000,#1001,#1002,
#1003,#1004,#1005,#1006,#1007,#1008,#1009,#1010,#1011,#1012,#1013,#1014,#1015,#1016,#1017,#1018,
#1019,#1020,#1021,#1022,#1023,#1024,#1025,#1026,#1027,#1028,#1029,#1030,#1031,#1032,#1033,#1034,
#1035,#1036,#1037,#1038,#1039,#1040,#1041,#1042,#1043,#1044),.UNSPECIFIED.,.F.,.F.,(4,2,2,2,2,2,
2,2,2,2,2,2,2,2,2,2,2,2,2,2,2,2,2,2,2,4),(0.,2.4398667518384,4.87974015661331,7.31965051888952,
9.75955957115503,12.2069944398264,14.6544259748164,17.1019486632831,19.5494721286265,
21.9776359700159,24.4058016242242,29.2617583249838,31.6862315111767,34.1106932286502,
36.5350965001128,38.959500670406,40.879292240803,42.7991023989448,46.6387702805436,
50.4830954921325,54.327351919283,58.1962585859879,62.0651889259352,65.9262209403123,
67.8566955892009,69.7871680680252),.UNSPECIFIED.);
#1046=CARTESIAN_POINT('',(-34.7560813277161,-17.05,28.0740326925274));
#1047=VERTEX_POINT('',#1046);
#1048=EDGE_CURVE('E912',#990,#1047,#1045,.T.);
#1049=ORIENTED_EDGE('',*,*,#1048,.T.);
#1050=DIRECTION('',(0.,0.,-1.));
#1051=VECTOR('',#1050,1.);
#1052=CARTESIAN_POINT('',(-34.7560813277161,-17.05,0.));
#1053=LINE('',#1052,#1051);
#1054=EDGE_CURVE('E936',#1047,#494,#1053,.T.);
#1055=ORIENTED_EDGE('',*,*,#1054,.T.);
#1056=ORIENTED_EDGE('',*,*,#730,.F.);
#1057=EDGE_LOOP('',(#992,#1049,#1055,#1056));
#1058=FACE_BOUND('',#1057,.T.);
#1059=ADVANCED_FACE('F420',(#1058),#984,.F.);
#1060=CARTESIAN_POINT('',(-34.7560813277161,-19.8055555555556,0.));
#1061=DIRECTION('',(0.,0.,-1.));
#1062=DIRECTION('',(0.,1.,0.));
#1063=AXIS2_PLACEMENT_3D('',#1060,#1061,#1062);
#1064=CYLINDRICAL_SURFACE('',#1063,2.75555555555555);
#1065=ORIENTED_EDGE('',*,*,#495,.F.);
#1066=ORIENTED_EDGE('',*,*,#1054,.F.);
#1067=CARTESIAN_POINT('',(-37.1502057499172,-21.1698336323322,28.6098003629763));
#1068=CARTESIAN_POINT('',(-37.1883688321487,-21.1028781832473,28.6098011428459));
#1069=CARTESIAN_POINT('',(-37.2237075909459,-21.0343175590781,28.6093997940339));
#1070=CARTESIAN_POINT('',(-37.2885175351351,-20.8944908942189,28.6077989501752));
#1071=CARTESIAN_POINT('',(-37.3179890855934,-20.8232250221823,28.6065995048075));
#1072=CARTESIAN_POINT('',(-37.370826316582,-20.6785505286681,28.6034100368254));
#1073=CARTESIAN_POINT('',(-37.3941975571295,-20.6051439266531,28.601420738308));
#1074=CARTESIAN_POINT('',(-37.4347106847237,-20.4566780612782,28.5966657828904));
#1075=CARTESIAN_POINT('',(-37.4518526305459,-20.3816188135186,28.5939001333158));
#1076=CARTESIAN_POINT('',(-37.493745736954,-20.1546855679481,28.5844579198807));
#1077=CARTESIAN_POINT('',(-37.5089901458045,-20.0009847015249,28.5766345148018));
#1078=CARTESIAN_POINT('',(-37.5136533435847,-19.6934729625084,28.5581350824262));
#1079=CARTESIAN_POINT('',(-37.5030757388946,-19.5396621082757,28.5474594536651));
#1080=CARTESIAN_POINT('',(-37.4564492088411,-19.2356321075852,28.5234764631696));
#1081=CARTESIAN_POINT('',(-37.4203182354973,-19.0854261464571,28.5101607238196));
#1082=CARTESIAN_POINT('',(-37.3235993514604,-18.7933206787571,28.4812492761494));
#1083=CARTESIAN_POINT('',(-37.2630068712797,-18.6514227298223,28.4656531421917));
#1084=CARTESIAN_POINT('',(-37.1186316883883,-18.3788839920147,28.4324524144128));
#1085=CARTESIAN_POINT('',(-37.0346844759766,-18.2483320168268,28.4148341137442));
#1086=CARTESIAN_POINT('',(-36.8462416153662,-18.003277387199,28.3781353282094));
#1087=CARTESIAN_POINT('',(-36.741748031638,-17.8887731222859,28.3590549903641));
#1088=CARTESIAN_POINT('',(-36.5143467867,-17.6781670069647,28.3197834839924));
#1089=CARTESIAN_POINT('',(-36.3913101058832,-17.5822057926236,28.2995852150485));
#1090=CARTESIAN_POINT('',(-36.1308129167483,-17.4123606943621,28.2587412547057));
#1091=CARTESIAN_POINT('',(-35.9933452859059,-17.338487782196,28.238095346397));
#1092=CARTESIAN_POINT('',(-35.7071707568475,-17.214614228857,28.1968337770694));
#1093=CARTESIAN_POINT('',(-35.5584070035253,-17.1647450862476,28.1762188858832));
#1094=CARTESIAN_POINT('',(-35.2546544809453,-17.090994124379,28.1357549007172));
#1095=CARTESIAN_POINT('',(-35.0996787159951,-17.0670606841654,28.1159043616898));
#1096=CARTESIAN_POINT('',(-34.9126769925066,-17.0542732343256,28.0929069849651));
#1097=CARTESIAN_POINT('',(-34.8813632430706,-17.0526702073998,28.0890879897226));
#1098=CARTESIAN_POINT('',(-34.8187312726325,-17.0505350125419,28.0815134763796));
#1099=CARTESIAN_POINT('',(-34.7874131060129,-17.0500015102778,28.0777578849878));
#1100=CARTESIAN_POINT('',(-34.7560813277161,-17.05,28.0740326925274));
#1101=B_SPLINE_CURVE_WITH_KNOTS('',3,(#1067,#1068,#1069,#1070,#1071,#1072,#1073,#1074,#1075,
#1076,#1077,#1078,#1079,#1080,#1081,#1082,#1083,#1084,#1085,#1086,#1087,#1088,#1089,#1090,#1091,
#1092,#1093,#1094,#1095,#1096,#1097,#1098,#1099,#1100),.UNSPECIFIED.,.F.,.F.,(4,2,2,2,2,2,2,2,2,
2,2,2,2,2,2,2,4),(0.,0.231127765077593,0.462241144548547,0.693143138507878,0.924042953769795,
1.38561756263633,1.84712771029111,2.31012646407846,2.77321174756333,3.23964538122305,
3.70603217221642,4.17582815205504,4.64585710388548,5.11843248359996,5.59006553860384,
5.68481681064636,5.77944979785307),.UNSPECIFIED.);
#1102=CARTESIAN_POINT('',(-37.1502057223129,-21.1698336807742,28.6098003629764));
#1103=VERTEX_POINT('',#1102);
#1104=EDGE_CURVE('E404',#1103,#1047,#1101,.T.);
#1105=ORIENTED_EDGE('',*,*,#1104,.F.);
#1106=DIRECTION('',(0.,0.,-1.));
#1107=VECTOR('',#1106,1.);
#1108=CARTESIAN_POINT('',(-37.1502057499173,-21.1698336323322,0.));
#1109=LINE('',#1108,#1107);
#1110=EDGE_CURVE('E928',#1103,#354,#1109,.T.);
#1111=ORIENTED_EDGE('',*,*,#1110,.T.);
#1112=ORIENTED_EDGE('',*,*,#355,.T.);
#1113=EDGE_LOOP('',(#1065,#1066,#1105,#1111,#1112));
#1114=FACE_BOUND('',#1113,.T.);
#1115=ADVANCED_FACE('F374',(#1114),#1064,.F.);
#1116=CARTESIAN_POINT('',(0.,0.,0.));
#1117=DIRECTION('',(0.,0.,-1.));
#1118=DIRECTION('',(0.,1.,0.));
#1119=AXIS2_PLACEMENT_3D('',#1116,#1117,#1118);
#1120=CYLINDRICAL_SURFACE('',#1119,42.7586206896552);
#1121=ORIENTED_EDGE('',*,*,#1110,.F.);
#1122=CARTESIAN_POINT('',(0.,0.,28.6098003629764));
#1123=DIRECTION('',(0.,0.,-1.));
#1124=DIRECTION('',(0.,1.,0.));
#1125=AXIS2_PLACEMENT_3D('',#1122,#1123,#1124);
#1126=CIRCLE('',#1125,42.7586206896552);
#1127=CARTESIAN_POINT('',(37.1502056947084,-21.1698337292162,28.6098003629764));
#1128=VERTEX_POINT('',#1127);
#1129=EDGE_CURVE('E927',#1128,#1103,#1126,.T.);
#1130=ORIENTED_EDGE('',*,*,#1129,.F.);
#1131=DIRECTION('',(0.,0.,-1.));
#1132=VECTOR('',#1131,1.);
#1133=CARTESIAN_POINT('',(37.1502056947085,-21.1698337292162,0.));
#1134=LINE('',#1133,#1132);
#1135=EDGE_CURVE('E456',#363,#1128,#1134,.F.);
#1136=ORIENTED_EDGE('',*,*,#1135,.F.);
#1137=ORIENTED_EDGE('',*,*,#364,.T.);
#1138=EDGE_LOOP('',(#1121,#1130,#1136,#1137));
#1139=FACE_BOUND('',#1138,.T.);
#1140=ADVANCED_FACE('F471',(#1139),#1120,.F.);
#1141=CARTESIAN_POINT('',(34.7560813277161,-19.8055555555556,0.));
#1142=DIRECTION('',(0.,0.,-1.));
#1143=DIRECTION('',(0.,1.,0.));
#1144=AXIS2_PLACEMENT_3D('',#1141,#1142,#1143);
#1145=CYLINDRICAL_SURFACE('',#1144,2.75555555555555);
#1146=ORIENTED_EDGE('',*,*,#1135,.T.);
#1147=CARTESIAN_POINT('',(34.7560813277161,-17.05,28.0740326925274));
#1148=CARTESIAN_POINT('',(34.8342764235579,-17.0499928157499,28.0833292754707));
#1149=CARTESIAN_POINT('',(34.912443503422,-17.0533284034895,28.0928232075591));
#1150=CARTESIAN_POINT('',(35.0681681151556,-17.0666169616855,28.1121307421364));
#1151=CARTESIAN_POINT('',(35.1457256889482,-17.076569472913,28.1219443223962));
#1152=CARTESIAN_POINT('',(35.2996318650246,-17.1030139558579,28.1418100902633));
#1153=CARTESIAN_POINT('',(35.3759813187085,-17.1195010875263,28.151862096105));
#1154=CARTESIAN_POINT('',(35.5269663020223,-17.1588749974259,28.1721329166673));
#1155=CARTESIAN_POINT('',(35.601601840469,-17.181761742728,28.1823517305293));
#1156=CARTESIAN_POINT('',(35.8222026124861,-17.2598233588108,28.2131553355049));
#1157=CARTESIAN_POINT('',(35.9649431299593,-17.3244136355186,28.2338977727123));
#1158=CARTESIAN_POINT('',(36.2373723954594,-17.4767678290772,28.2751571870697));
#1159=CARTESIAN_POINT('',(36.3670632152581,-17.5645280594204,28.2956741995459));
#1160=CARTESIAN_POINT('',(36.610001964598,-17.7609330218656,28.3359641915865));
#1161=CARTESIAN_POINT('',(36.7232266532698,-17.8696067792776,28.355736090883));
#1162=CARTESIAN_POINT('',(36.9297252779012,-18.104718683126,28.393972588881));
#1163=CARTESIAN_POINT('',(37.0229964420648,-18.2311592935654,28.4124370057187));
#1164=CARTESIAN_POINT('',(37.1865401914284,-18.4977610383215,28.4475083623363));
#1165=CARTESIAN_POINT('',(37.2568904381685,-18.6378737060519,28.4641214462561));
#1166=CARTESIAN_POINT('',(37.3728975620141,-18.9281808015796,28.4951291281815));
#1167=CARTESIAN_POINT('',(37.4185589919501,-19.0783733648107,28.5095241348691));
#1168=CARTESIAN_POINT('',(37.4835428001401,-19.3834322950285,28.5356334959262));
#1169=CARTESIAN_POINT('',(37.5030533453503,-19.5382569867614,28.5473664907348));
#1170=CARTESIAN_POINT('',(37.5156824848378,-19.8492528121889,28.5679923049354));
#1171=CARTESIAN_POINT('',(37.5087888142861,-20.0054245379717,28.5768838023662));
#1172=CARTESIAN_POINT('',(37.4688512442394,-20.3134317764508,28.5915441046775));
#1173=CARTESIAN_POINT('',(37.4359852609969,-20.465289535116,28.5973337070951));
#1174=CARTESIAN_POINT('',(37.3452383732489,-20.7611674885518,28.6057269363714));
#1175=CARTESIAN_POINT('',(37.2874126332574,-20.9052041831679,28.6083375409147));
#1176=CARTESIAN_POINT('',(37.1965257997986,-21.0860394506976,28.6096464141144));
#1177=CARTESIAN_POINT('',(37.173906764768,-21.1282584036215,28.6098012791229));
#1178=CARTESIAN_POINT('',(37.1502056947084,-21.1698337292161,28.6098003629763));
#1179=B_SPLINE_CURVE_WITH_KNOTS('',3,(#1147,#1148,#1149,#1150,#1151,#1152,#1153,#1154,#1155,
#1156,#1157,#1158,#1159,#1160,#1161,#1162,#1163,#1164,#1165,#1166,#1167,#1168,#1169,#1170,#1171,
#1172,#1173,#1174,#1175,#1176,#1177,#1178),.UNSPECIFIED.,.F.,.F.,(4,2,2,2,2,2,2,2,2,2,2,2,2,2,2,
4),(0.,0.23615869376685,0.472300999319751,0.708268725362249,0.944235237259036,1.41592240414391,
1.88753456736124,2.35980605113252,2.8321430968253,3.30286269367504,3.77349545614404,
4.24072329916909,4.70816819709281,5.1724384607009,5.63568783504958,5.77930499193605),.UNSPECIFIED.);
#1180=EDGE_CURVE('E447',#990,#1128,#1179,.T.);
#1181=ORIENTED_EDGE('',*,*,#1180,.F.);
#1182=ORIENTED_EDGE('',*,*,#991,.F.);
#1183=ORIENTED_EDGE('',*,*,#651,.F.);
#1184=ORIENTED_EDGE('',*,*,#387,.T.);
#1185=EDGE_LOOP('',(#1146,#1181,#1182,#1183,#1184));
#1186=FACE_BOUND('',#1185,.T.);
#1187=ADVANCED_FACE('F467',(#1186),#1145,.F.);
#1188=CARTESIAN_POINT('',(0.,0.,39.4643307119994));
#1189=DIRECTION('',(0.,0.,-1.));
#1190=DIRECTION('',(1.,0.,0.));
#1191=AXIS2_PLACEMENT_3D('',#1188,#1189,#1190);
#1192=CONICAL_SURFACE('',#1191,61.2503681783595,0.26179938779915);
#1193=ORIENTED_EDGE('',*,*,#747,.F.);
#1194=EDGE_LOOP('',(#1193));
#1195=FACE_BOUND('',#1194,.T.);
#1196=CARTESIAN_POINT('',(0.,0.,42.3694018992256));
#1197=DIRECTION('',(0.,0.,-1.));
#1198=DIRECTION('',(-1.,0.,0.));
#1199=AXIS2_PLACEMENT_3D('',#1196,#1197,#1198);
#1200=CIRCLE('',#1199,60.4719566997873);
#1201=CARTESIAN_POINT('',(-60.4719566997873,0.,42.3694018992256));
#1202=VERTEX_POINT('',#1201);
#1203=EDGE_CURVE('E610',#1202,#1202,#1200,.T.);
#1204=ORIENTED_EDGE('',*,*,#1203,.T.);
#1205=EDGE_LOOP('',(#1204));
#1206=FACE_BOUND('',#1205,.T.);
#1207=ADVANCED_FACE('F416',(#1195,#1206),#1192,.T.);
#1208=CARTESIAN_POINT('',(0.,0.,28.8120300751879));
#1209=DIRECTION('',(0.,0.,1.));
#1210=DIRECTION('',(-1.,0.,0.));
#1211=AXIS2_PLACEMENT_3D('',#1208,#1209,#1210);
#1212=CONICAL_SURFACE('',#1211,44.2857142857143,1.43913457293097);
#1213=CARTESIAN_POINT('',(43.7627551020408,6.78570229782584,28.8120300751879));
#1214=CARTESIAN_POINT('',(43.5722525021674,6.66677246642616,28.7846881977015));
#1215=CARTESIAN_POINT('',(43.386728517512,6.53974942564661,28.757866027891));
#1216=CARTESIAN_POINT('',(43.0269006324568,6.2704611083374,28.7054998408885));
#1217=CARTESIAN_POINT('',(42.8525967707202,6.12819577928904,28.6799558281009));
#1218=CARTESIAN_POINT('',(42.5165096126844,5.82940017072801,28.6303902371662));
#1219=CARTESIAN_POINT('',(42.3547236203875,5.67287297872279,28.6063683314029));
#1220=CARTESIAN_POINT('',(42.0448019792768,5.34660948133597,28.5600777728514));
#1221=CARTESIAN_POINT('',(41.896665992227,5.17687350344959,28.537809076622));
#1222=CARTESIAN_POINT('',(41.6150229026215,4.82523056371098,28.4952386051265));
#1223=CARTESIAN_POINT('',(41.4815266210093,4.64331475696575,28.4749382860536));
#1224=CARTESIAN_POINT('',(41.2302790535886,4.26869352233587,28.4365429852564));
#1225=CARTESIAN_POINT('',(41.1125278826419,4.07598801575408,28.4184480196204));
#1226=CARTESIAN_POINT('',(40.8936994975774,3.68122333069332,28.3846747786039));
#1227=CARTESIAN_POINT('',(40.7926160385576,3.47916769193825,28.3689955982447));
#1228=CARTESIAN_POINT('',(40.6078406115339,3.0670781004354,28.3402303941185));
#1229=CARTESIAN_POINT('',(40.5241484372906,2.85704424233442,28.3271443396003));
#1230=CARTESIAN_POINT('',(40.3753573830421,2.43210298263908,28.3038120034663));
#1231=CARTESIAN_POINT('',(40.3101243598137,2.2172436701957,28.2935452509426));
#1232=CARTESIAN_POINT('',(40.1979057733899,1.7826150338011,28.2758466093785));
#1233=CARTESIAN_POINT('',(40.1509266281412,1.56284401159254,28.268415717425));
#1234=CARTESIAN_POINT('',(40.0756197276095,1.12009470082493,28.2564889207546));
#1235=CARTESIAN_POINT('',(40.047288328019,0.897117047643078,28.25199244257));
#1236=CARTESIAN_POINT('',(40.0094742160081,0.449426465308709,28.2459883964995));
#1237=CARTESIAN_POINT('',(40.0000000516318,0.22471279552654,28.2444821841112));
#1238=CARTESIAN_POINT('',(39.9999999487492,-0.22305467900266,28.2444821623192));
#1239=CARTESIAN_POINT('',(40.0093347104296,-0.44610849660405,28.2459662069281));
#1240=CARTESIAN_POINT('',(40.0465931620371,-0.890515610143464,28.2518821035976));
#1241=CARTESIAN_POINT('',(40.0745083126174,-1.11186964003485,28.2563126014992));
#1242=CARTESIAN_POINT('',(40.1487099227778,-1.55142853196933,28.2680649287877));
#1243=CARTESIAN_POINT('',(40.1949988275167,-1.76963297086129,28.2753871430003));
#1244=CARTESIAN_POINT('',(40.3055755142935,-2.20123648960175,28.2928287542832));
#1245=CARTESIAN_POINT('',(40.3698570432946,-2.41463721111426,28.3029471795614));
#1246=CARTESIAN_POINT('',(40.515925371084,-2.83516533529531,28.3258569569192));
#1247=CARTESIAN_POINT('',(40.5977087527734,-3.04229395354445,28.3386477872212));
#1248=CARTESIAN_POINT('',(40.7781760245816,-3.44887342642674,28.3667522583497));
#1249=CARTESIAN_POINT('',(40.8768599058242,-3.64832428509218,28.3820658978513));
#1250=CARTESIAN_POINT('',(41.0904423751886,-4.0382480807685,28.4150476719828));
#1251=CARTESIAN_POINT('',(41.205347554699,-4.22871732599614,28.4327167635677));
#1252=CARTESIAN_POINT('',(41.4505009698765,-4.59928479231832,28.4702098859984));
#1253=CARTESIAN_POINT('',(41.5807493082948,-4.77938294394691,28.4900339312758));
#1254=CARTESIAN_POINT('',(41.86074646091,-5.13444773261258,28.5323989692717));
#1255=CARTESIAN_POINT('',(42.0110388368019,-5.30897728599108,28.5550133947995));
#1256=CARTESIAN_POINT('',(42.3259710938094,-5.64431731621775,28.6020913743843));
#1257=CARTESIAN_POINT('',(42.490611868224,-5.80512693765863,28.6265550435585));
#1258=CARTESIAN_POINT('',(42.8330842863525,-6.11194217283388,28.6770919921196));
#1259=CARTESIAN_POINT('',(43.0109229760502,-6.25793977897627,28.7031661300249));
#1260=CARTESIAN_POINT('',(43.3783574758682,-6.53401354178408,28.7566557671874));
#1261=CARTESIAN_POINT('',(43.5679528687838,-6.6640902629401,28.7840712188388));
#1262=CARTESIAN_POINT('',(43.7627551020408,-6.78570229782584,28.8120300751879));
#1263=B_SPLINE_CURVE_WITH_KNOTS('',3,(#1213,#1214,#1215,#1216,#1217,#1218,#1219,#1220,#1221,
#1222,#1223,#1224,#1225,#1226,#1227,#1228,#1229,#1230,#1231,#1232,#1233,#1234,#1235,#1236,#1237,
#1238,#1239,#1240,#1241,#1242,#1243,#1244,#1245,#1246,#1247,#1248,#1249,#1250,#1251,#1252,#1253,
#1254,#1255,#1256,#1257,#1258,#1259,#1260,#1261,#1262),.UNSPECIFIED.,.F.,.F.,(4,2,2,2,2,2,2,2,2,
2,2,2,2,2,2,2,2,2,2,2,2,2,2,2,4),(0.,0.678512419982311,1.35702717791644,2.03539539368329,
2.71374679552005,3.39259626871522,4.07145069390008,4.75005019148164,5.42864164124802,
6.10216708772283,6.77592912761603,7.44955945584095,8.12349507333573,8.79245783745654,
9.46111336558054,10.1298579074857,10.7983703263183,11.4667523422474,12.1351340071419,
12.8037880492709,13.4724465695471,14.1658694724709,14.8593355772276,15.5531746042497,
16.2469890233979),.UNSPECIFIED.);
#1264=CARTESIAN_POINT('',(43.7627551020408,6.78570229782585,28.8120300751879));
#1265=VERTEX_POINT('',#1264);
#1266=CARTESIAN_POINT('',(43.7627551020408,-6.78570229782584,28.8120300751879));
#1267=VERTEX_POINT('',#1266);
#1268=EDGE_CURVE('E426',#1265,#1267,#1263,.T.);
#1269=ORIENTED_EDGE('',*,*,#1268,.F.);
#1270=CARTESIAN_POINT('',(0.,0.,28.8120300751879));
#1271=DIRECTION('',(0.,0.,1.));
#1272=DIRECTION('',(-1.,0.,0.));
#1273=AXIS2_PLACEMENT_3D('',#1270,#1271,#1272);
#1274=CIRCLE('',#1273,44.2857142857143);
#1275=EDGE_CURVE('E911',#1267,#1265,#1274,.F.);
#1276=ORIENTED_EDGE('',*,*,#1275,.F.);
#1277=EDGE_LOOP('',(#1269,#1276));
#1278=FACE_BOUND('',#1277,.T.);
#1279=ORIENTED_EDGE('',*,*,#1180,.T.);
#1280=ORIENTED_EDGE('',*,*,#1129,.T.);
#1281=ORIENTED_EDGE('',*,*,#1104,.T.);
#1282=ORIENTED_EDGE('',*,*,#1048,.F.);
#1283=EDGE_LOOP('',(#1279,#1280,#1281,#1282));
#1284=FACE_BOUND('',#1283,.T.);
#1285=ORIENTED_EDGE('',*,*,#975,.F.);
#1286=EDGE_LOOP('',(#1285));
#1287=FACE_BOUND('',#1286,.T.);
#1288=ORIENTED_EDGE('',*,*,#958,.T.);
#1289=ORIENTED_EDGE('',*,*,#909,.T.);
#1290=ORIENTED_EDGE('',*,*,#836,.T.);
#1291=ORIENTED_EDGE('',*,*,#782,.T.);
#1292=EDGE_LOOP('',(#1288,#1289,#1290,#1291));
#1293=FACE_BOUND('',#1292,.T.);
#1294=ADVANCED_FACE('F410',(#1278,#1284,#1287,#1293),#1212,.F.);
#1295=CARTESIAN_POINT('',(0.,0.,30.9929893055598));
#1296=DIRECTION('',(0.,0.,-1.));
#1297=DIRECTION('',(0.,1.,0.));
#1298=AXIS2_PLACEMENT_3D('',#1295,#1296,#1297);
#1299=TOROIDAL_SURFACE('',#1298,43.9968945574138,2.19999999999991);
#1300=ORIENTED_EDGE('',*,*,#1275,.T.);
#1301=CARTESIAN_POINT('',(45.5560379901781,7.6175487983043,30.801246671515));
#1302=CARTESIAN_POINT('',(45.5509279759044,7.61590416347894,30.7404671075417));
#1303=CARTESIAN_POINT('',(45.5433730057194,7.61347965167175,30.6799168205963));
#1304=CARTESIAN_POINT('',(45.523468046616,7.60703094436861,30.5596972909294));
#1305=CARTESIAN_POINT('',(45.5111181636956,7.60300678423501,30.5000280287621));
#1306=CARTESIAN_POINT('',(45.4817241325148,7.59332078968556,30.3820147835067));
#1307=CARTESIAN_POINT('',(45.4646819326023,7.58765963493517,30.3236702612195));
#1308=CARTESIAN_POINT('',(45.4260634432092,7.57464616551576,30.2087145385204));
#1309=CARTESIAN_POINT('',(45.4044872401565,7.56729388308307,30.1521033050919));
#1310=CARTESIAN_POINT('',(45.333180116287,7.54258722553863,29.9853985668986));
#1311=CARTESIAN_POINT('',(45.2768645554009,7.52258111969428,29.8784096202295));
#1312=CARTESIAN_POINT('',(45.1488113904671,7.47498239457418,29.6761229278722));
#1313=CARTESIAN_POINT('',(45.0770810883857,7.44739336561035,29.5808196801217));
#1314=CARTESIAN_POINT('',(44.9211781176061,7.3842993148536,29.4048556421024));
#1315=CARTESIAN_POINT('',(44.8370658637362,7.34883232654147,29.3241277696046));
#1316=CARTESIAN_POINT('',(44.6592346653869,7.26971387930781,29.1788050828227));
#1317=CARTESIAN_POINT('',(44.5655110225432,7.22605840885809,29.114218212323));
#1318=CARTESIAN_POINT('',(44.3714310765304,7.13058511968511,29.0022343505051));
#1319=CARTESIAN_POINT('',(44.271043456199,7.0787269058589,28.9549264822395));
#1320=CARTESIAN_POINT('',(44.067613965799,6.96776127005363,28.8784613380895));
#1321=CARTESIAN_POINT('',(43.9645763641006,6.90866499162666,28.8492765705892));
#1322=CARTESIAN_POINT('',(43.8287239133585,6.82656498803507,28.8223825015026));
#1323=CARTESIAN_POINT('',(43.7957003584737,6.806279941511,28.816752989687));
#1324=CARTESIAN_POINT('',(43.7627551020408,6.78570229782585,28.812030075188));
#1325=B_SPLINE_CURVE_WITH_KNOTS('',3,(#1301,#1302,#1303,#1304,#1305,#1306,#1307,#1308,#1309,
#1310,#1311,#1312,#1313,#1314,#1315,#1316,#1317,#1318,#1319,#1320,#1321,#1322,#1323,#1324),
.UNSPECIFIED.,.F.,.F.,(4,2,2,2,2,2,2,2,2,2,2,4),(0.,0.182989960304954,0.365975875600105,
0.548885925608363,0.731792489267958,1.09753086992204,1.46309638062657,1.82693394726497,
2.19095022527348,2.5568183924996,2.9221301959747,3.03956319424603),.UNSPECIFIED.);
#1326=CARTESIAN_POINT('',(45.5560379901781,7.6175487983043,30.801246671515));
#1327=VERTEX_POINT('',#1326);
#1328=EDGE_CURVE('E578',#1327,#1265,#1325,.T.);
#1329=ORIENTED_EDGE('',*,*,#1328,.F.);
#1330=CARTESIAN_POINT('',(0.,0.,30.801246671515));
#1331=DIRECTION('',(0.,0.,-1.));
#1332=DIRECTION('',(0.,1.,0.));
#1333=AXIS2_PLACEMENT_3D('',#1330,#1331,#1332);
#1334=CIRCLE('',#1333,46.1885228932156);
#1335=CARTESIAN_POINT('',(45.5560379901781,-7.61754879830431,30.801246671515));
#1336=VERTEX_POINT('',#1335);
#1337=EDGE_CURVE('E903',#1336,#1327,#1334,.T.);
#1338=ORIENTED_EDGE('',*,*,#1337,.F.);
#1339=CARTESIAN_POINT('',(43.7627551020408,-6.78570229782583,28.812030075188));
#1340=CARTESIAN_POINT('',(43.8164597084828,-6.81924529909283,28.8197319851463));
#1341=CARTESIAN_POINT('',(43.8703301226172,-6.85198999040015,28.8298271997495));
#1342=CARTESIAN_POINT('',(43.9779986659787,-6.91573518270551,28.8548773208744));
#1343=CARTESIAN_POINT('',(44.0317967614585,-6.94673503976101,28.8698340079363));
#1344=CARTESIAN_POINT('',(44.1389486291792,-7.00685848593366,28.9046979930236));
#1345=CARTESIAN_POINT('',(44.1923017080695,-7.03597950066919,28.9246119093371));
#1346=CARTESIAN_POINT('',(44.2979914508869,-7.09215920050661,28.969357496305));
#1347=CARTESIAN_POINT('',(44.3503282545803,-7.11921817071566,28.9941884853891));
#1348=CARTESIAN_POINT('',(44.505368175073,-7.19728376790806,29.0761464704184));
#1349=CARTESIAN_POINT('',(44.6059150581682,-7.24507591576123,29.14067899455));
#1350=CARTESIAN_POINT('',(44.7968203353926,-7.33148402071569,29.2879562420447));
#1351=CARTESIAN_POINT('',(44.8871925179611,-7.3701124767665,29.3706758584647));
#1352=CARTESIAN_POINT('',(45.0506723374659,-7.43699834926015,29.5482031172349));
#1353=CARTESIAN_POINT('',(45.12435137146,-7.46562741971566,29.6423458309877));
#1354=CARTESIAN_POINT('',(45.2564827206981,-7.51519280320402,29.8427799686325));
#1355=CARTESIAN_POINT('',(45.3149214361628,-7.53612225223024,29.9490821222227));
#1356=CARTESIAN_POINT('',(45.3906983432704,-7.56255908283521,30.1178916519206));
#1357=CARTESIAN_POINT('',(45.4143803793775,-7.5706716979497,30.1772422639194));
#1358=CARTESIAN_POINT('',(45.4567268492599,-7.58500245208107,30.2979521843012));
#1359=CARTESIAN_POINT('',(45.4753909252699,-7.59122045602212,30.3593116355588));
#1360=CARTESIAN_POINT('',(45.5075091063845,-7.60182755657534,30.4835547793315));
#1361=CARTESIAN_POINT('',(45.5209611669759,-7.60621593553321,30.5464390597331));
#1362=CARTESIAN_POINT('',(45.5425297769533,-7.61320844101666,30.6732126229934));
#1363=CARTESIAN_POINT('',(45.5506464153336,-7.61581259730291,30.7371018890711));
#1364=CARTESIAN_POINT('',(45.5560379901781,-7.6175487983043,30.801246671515));
#1365=B_SPLINE_CURVE_WITH_KNOTS('',3,(#1339,#1340,#1341,#1342,#1343,#1344,#1345,#1346,#1347,
#1348,#1349,#1350,#1351,#1352,#1353,#1354,#1355,#1356,#1357,#1358,#1359,#1360,#1361,#1362,#1363,
#1364),.UNSPECIFIED.,.F.,.F.,(4,2,2,2,2,2,2,2,2,2,2,2,4),(0.,0.191320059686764,
0.382710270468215,0.574357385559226,0.765977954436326,1.14987233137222,1.53324004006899,
1.90027904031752,2.26764445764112,2.46067291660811,2.6537151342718,2.84683299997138,
3.03994764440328),.UNSPECIFIED.);
#1366=EDGE_CURVE('E870',#1267,#1336,#1365,.T.);
#1367=ORIENTED_EDGE('',*,*,#1366,.F.);
#1368=EDGE_LOOP('',(#1300,#1329,#1338,#1367));
#1369=FACE_BOUND('',#1368,.T.);
#1370=ADVANCED_FACE('F415',(#1369),#1299,.F.);
#1371=CARTESIAN_POINT('',(0.,0.,39.7560545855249));
#1372=DIRECTION('',(0.,0.,1.));
#1373=DIRECTION('',(-1.,0.,0.));
#1374=AXIS2_PLACEMENT_3D('',#1371,#1372,#1373);
#1375=CONICAL_SURFACE('',#1374,46.9719670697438,0.0872664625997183);
#1376=ORIENTED_EDGE('',*,*,#1337,.T.);
#1377=CARTESIAN_POINT('',(46.3163092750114,7.82081744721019,39.7560545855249));
#1378=CARTESIAN_POINT('',(46.1885271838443,7.79333517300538,38.2635322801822));
#1379=CARTESIAN_POINT('',(46.0612801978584,7.76265498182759,36.7710371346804));
#1380=CARTESIAN_POINT('',(45.8078564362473,7.6948987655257,33.7861011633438));
#1381=CARTESIAN_POINT('',(45.6816796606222,7.65782274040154,32.2936603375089));
#1382=CARTESIAN_POINT('',(45.5560379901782,7.61754879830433,30.801246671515));
#1383=B_SPLINE_CURVE_WITH_KNOTS('',3,(#1377,#1378,#1379,#1380,#1381,#1382),.UNSPECIFIED.,.F.,
.F.,(4,2,4),(0.,4.494671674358,8.98934334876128),.UNSPECIFIED.);
#1384=CARTESIAN_POINT('',(46.3163092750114,7.82081744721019,39.7560545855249));
#1385=VERTEX_POINT('',#1384);
#1386=EDGE_CURVE('E855',#1385,#1327,#1383,.T.);
#1387=ORIENTED_EDGE('',*,*,#1386,.F.);
#1388=CARTESIAN_POINT('',(0.,0.,39.7560545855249));
#1389=DIRECTION('',(0.,0.,1.));
#1390=DIRECTION('',(-1.,0.,0.));
#1391=AXIS2_PLACEMENT_3D('',#1388,#1389,#1390);
#1392=CIRCLE('',#1391,46.9719670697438);
#1393=CARTESIAN_POINT('',(46.3163092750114,-7.82081744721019,39.7560545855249));
#1394=VERTEX_POINT('',#1393);
#1395=EDGE_CURVE('E651',#1394,#1385,#1392,.F.);
#1396=ORIENTED_EDGE('',*,*,#1395,.F.);
#1397=CARTESIAN_POINT('',(45.5560379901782,-7.61754879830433,30.801246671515));
#1398=CARTESIAN_POINT('',(45.6816796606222,-7.65782274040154,32.2936603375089));
#1399=CARTESIAN_POINT('',(45.8078564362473,-7.6948987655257,33.7861011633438));
#1400=CARTESIAN_POINT('',(46.0612801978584,-7.76265498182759,36.7710371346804));
#1401=CARTESIAN_POINT('',(46.1885271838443,-7.79333517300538,38.2635322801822));
#1402=CARTESIAN_POINT('',(46.3163092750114,-7.82081744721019,39.7560545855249));
#1403=B_SPLINE_CURVE_WITH_KNOTS('',3,(#1397,#1398,#1399,#1400,#1401,#1402),.UNSPECIFIED.,.F.,
.F.,(4,2,4),(0.,4.49467167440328,8.98934334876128),.UNSPECIFIED.);
#1404=EDGE_CURVE('E892',#1336,#1394,#1403,.T.);
#1405=ORIENTED_EDGE('',*,*,#1404,.F.);
#1406=EDGE_LOOP('',(#1376,#1387,#1396,#1405));
#1407=FACE_BOUND('',#1406,.T.);
#1408=ADVANCED_FACE('F511',(#1407),#1375,.F.);
#1409=CARTESIAN_POINT('',(0.,0.,41.8));
#1410=DIRECTION('',(0.,0.,-1.));
#1411=DIRECTION('',(0.,1.,0.));
#1412=AXIS2_PLACEMENT_3D('',#1409,#1410,#1411);
#1413=TOROIDAL_SURFACE('',#1412,58.3469198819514,2.2);
#1414=ORIENTED_EDGE('',*,*,#1203,.F.);
#1415=EDGE_LOOP('',(#1414));
#1416=FACE_BOUND('',#1415,.T.);
#1417=CARTESIAN_POINT('',(0.,0.,44.));
#1418=DIRECTION('',(0.,0.,-1.));
#1419=DIRECTION('',(0.,-1.,0.));
#1420=AXIS2_PLACEMENT_3D('',#1417,#1418,#1419);
#1421=CIRCLE('',#1420,58.3469198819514);
#1422=CARTESIAN_POINT('',(0.,-58.3469198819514,44.));
#1423=VERTEX_POINT('',#1422);
#1424=CARTESIAN_POINT('',(-58.3469198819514,0.,44.));
#1425=VERTEX_POINT('',#1424);
#1426=EDGE_CURVE('E638',#1423,#1425,#1421,.T.);
#1427=ORIENTED_EDGE('',*,*,#1426,.T.);
#1428=CARTESIAN_POINT('',(0.,0.,44.));
#1429=DIRECTION('',(0.,0.,-1.));
#1430=DIRECTION('',(-1.,0.,0.));
#1431=AXIS2_PLACEMENT_3D('',#1428,#1429,#1430);
#1432=CIRCLE('',#1431,58.3469198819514);
#1433=CARTESIAN_POINT('',(0.,58.3469198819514,44.));
#1434=VERTEX_POINT('',#1433);
#1435=EDGE_CURVE('E641',#1425,#1434,#1432,.T.);
#1436=ORIENTED_EDGE('',*,*,#1435,.T.);
#1437=CARTESIAN_POINT('',(0.,0.,44.));
#1438=DIRECTION('',(0.,0.,-1.));
#1439=DIRECTION('',(0.,1.,0.));
#1440=AXIS2_PLACEMENT_3D('',#1437,#1438,#1439);
#1441=CIRCLE('',#1440,58.3469198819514);
#1442=EDGE_CURVE('E644',#1434,#1423,#1441,.T.);
#1443=ORIENTED_EDGE('',*,*,#1442,.T.);
#1444=EDGE_LOOP('',(#1427,#1436,#1443));
#1445=FACE_BOUND('',#1444,.T.);
#1446=ADVANCED_FACE('F613',(#1416,#1445),#1413,.T.);
#1447=CARTESIAN_POINT('',(48.,0.,33.7333333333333));
#1448=DIRECTION('',(0.,0.,1.));
#1449=DIRECTION('',(0.,-1.,0.));
#1450=AXIS2_PLACEMENT_3D('',#1447,#1448,#1449);
#1451=CYLINDRICAL_SURFACE('',#1450,8.);
#1452=CARTESIAN_POINT('',(46.3163092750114,-7.82081744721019,39.7560545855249));
#1453=CARTESIAN_POINT('',(46.3269325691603,-7.82308296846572,39.8802539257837));
#1454=CARTESIAN_POINT('',(46.3427443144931,-7.82648527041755,40.0039868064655));
#1455=CARTESIAN_POINT('',(46.38462653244,-7.83524830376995,40.24968024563));
#1456=CARTESIAN_POINT('',(46.4107007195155,-7.84060974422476,40.3716401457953));
#1457=CARTESIAN_POINT('',(46.4723435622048,-7.85284712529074,40.610385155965));
#1458=CARTESIAN_POINT('',(46.5077066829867,-7.85968977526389,40.727225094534));
#1459=CARTESIAN_POINT('',(46.5879545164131,-7.87450280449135,40.9574546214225));
#1460=CARTESIAN_POINT('',(46.63283471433,-7.88247264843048,41.0708458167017));
#1461=CARTESIAN_POINT('',(46.7298910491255,-7.89868029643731,41.288932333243));
#1462=CARTESIAN_POINT('',(46.7816980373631,-7.90689417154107,41.3937938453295));
#1463=CARTESIAN_POINT('',(46.8941715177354,-7.92340643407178,41.6000189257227));
#1464=CARTESIAN_POINT('',(46.9549216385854,-7.93170484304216,41.7013368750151));
#1465=CARTESIAN_POINT('',(47.0197678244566,-7.93971944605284,41.8));
#1466=B_SPLINE_CURVE_WITH_KNOTS('',3,(#1452,#1453,#1454,#1455,#1456,#1457,#1458,#1459,#1460,
#1461,#1462,#1463,#1464,#1465),.UNSPECIFIED.,.F.,.F.,(4,2,2,2,2,2,4),(0.,0.373905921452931,
0.747947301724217,1.11432293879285,1.48052516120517,1.8318945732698,2.18678730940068),.UNSPECIFIED.);
#1467=CARTESIAN_POINT('',(47.0197678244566,-7.93971944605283,41.8));
#1468=VERTEX_POINT('',#1467);
#1469=EDGE_CURVE('E885',#1394,#1468,#1466,.T.);
#1470=ORIENTED_EDGE('',*,*,#1469,.T.);
#1471=CARTESIAN_POINT('',(48.,0.,41.8));
#1472=DIRECTION('',(0.,0.,1.));
#1473=DIRECTION('',(0.,-1.,0.));
#1474=AXIS2_PLACEMENT_3D('',#1471,#1472,#1473);
#1475=CIRCLE('',#1474,8.);
#1476=CARTESIAN_POINT('',(47.0197678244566,7.93971944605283,41.8));
#1477=VERTEX_POINT('',#1476);
#1478=EDGE_CURVE('E891',#1468,#1477,#1475,.F.);
#1479=ORIENTED_EDGE('',*,*,#1478,.T.);
#1480=CARTESIAN_POINT('',(47.0197678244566,7.93971944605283,41.8));
#1481=CARTESIAN_POINT('',(46.9514446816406,7.93127313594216,41.6960515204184));
#1482=CARTESIAN_POINT('',(46.8876695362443,7.9225146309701,41.5891508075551));
#1483=CARTESIAN_POINT('',(46.7695175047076,7.90503184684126,41.3702345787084));
#1484=CARTESIAN_POINT('',(46.7151431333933,7.89630757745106,41.2582177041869));
#1485=CARTESIAN_POINT('',(46.6171424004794,7.87972807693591,41.0322455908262));
#1486=CARTESIAN_POINT('',(46.5733192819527,7.87185874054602,40.9183766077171));
#1487=CARTESIAN_POINT('',(46.4952524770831,7.85730933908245,40.6873823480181));
#1488=CARTESIAN_POINT('',(46.4610045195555,7.85062874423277,40.5702585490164));
#1489=CARTESIAN_POINT('',(46.4034278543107,7.83911999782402,40.3383084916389));
#1490=CARTESIAN_POINT('',(46.3797135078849,7.83422784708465,40.2235809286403));
#1491=CARTESIAN_POINT('',(46.3411514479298,7.82614481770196,39.9914054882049));
#1492=CARTESIAN_POINT('',(46.3263947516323,7.82297143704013,39.8739418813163));
#1493=CARTESIAN_POINT('',(46.3163092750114,7.82081744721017,39.7560545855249));
#1494=B_SPLINE_CURVE_WITH_KNOTS('',3,(#1480,#1481,#1482,#1483,#1484,#1485,#1486,#1487,#1488,
#1489,#1490,#1491,#1492,#1493),.UNSPECIFIED.,.F.,.F.,(4,2,2,2,2,2,4),(0.,0.373905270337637,
0.747910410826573,1.11428032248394,1.48048654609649,1.83188010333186,2.18678682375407),.UNSPECIFIED.);
#1495=EDGE_CURVE('E650',#1477,#1385,#1494,.T.);
#1496=ORIENTED_EDGE('',*,*,#1495,.T.);
#1497=ORIENTED_EDGE('',*,*,#1386,.T.);
#1498=ORIENTED_EDGE('',*,*,#1328,.T.);
#1499=ORIENTED_EDGE('',*,*,#1268,.T.);
#1500=ORIENTED_EDGE('',*,*,#1366,.T.);
#1501=ORIENTED_EDGE('',*,*,#1404,.T.);
#1502=EDGE_LOOP('',(#1470,#1479,#1496,#1497,#1498,#1499,#1500,#1501));
#1503=FACE_BOUND('',#1502,.T.);
#1504=ADVANCED_FACE('F209',(#1503),#1451,.T.);
#1505=CARTESIAN_POINT('',(0.,0.,44.));
#1506=DIRECTION('',(0.,0.,1.));
#1507=DIRECTION('',(-1.,0.,0.));
#1508=AXIS2_PLACEMENT_3D('',#1505,#1506,#1507);
#1509=CONICAL_SURFACE('',#1508,52.2600971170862,1.39626340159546);
#1510=CARTESIAN_POINT('',(0.,0.,44.));
#1511=DIRECTION('',(0.,0.,1.));
#1512=DIRECTION('',(-1.,0.,0.));
#1513=AXIS2_PLACEMENT_3D('',#1510,#1511,#1512);
#1514=CIRCLE('',#1513,52.2600971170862);
#1515=CARTESIAN_POINT('',(52.0987265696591,-4.10371057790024,44.));
#1516=VERTEX_POINT('',#1515);
#1517=CARTESIAN_POINT('',(51.9745338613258,-5.45578414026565,44.));
#1518=VERTEX_POINT('',#1517);
#1519=EDGE_CURVE('E160',#1516,#1518,#1514,.F.);
#1520=ORIENTED_EDGE('',*,*,#1519,.F.);
#1521=CARTESIAN_POINT('',(50.1652900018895,-6.55059837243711,43.7057234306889));
#1522=CARTESIAN_POINT('',(50.2491482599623,-6.49828433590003,43.7191910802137));
#1523=CARTESIAN_POINT('',(50.3316694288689,-6.44374292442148,43.7323946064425));
#1524=CARTESIAN_POINT('',(50.4939122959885,-6.33011620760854,43.7582572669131));
#1525=CARTESIAN_POINT('',(50.5736267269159,-6.27102021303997,43.7709150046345));
#1526=CARTESIAN_POINT('',(50.7297970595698,-6.14838966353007,43.7956161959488));
#1527=CARTESIAN_POINT('',(50.8062497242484,-6.08485085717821,43.8076590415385));
#1528=CARTESIAN_POINT('',(50.9578769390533,-5.95129013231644,43.8314431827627));
#1529=CARTESIAN_POINT('',(51.0329285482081,-5.88112438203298,43.8431618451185));
#1530=CARTESIAN_POINT('',(51.1785534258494,-5.73626277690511,43.8657905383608));
#1531=CARTESIAN_POINT('',(51.2491301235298,-5.66157047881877,43.8767011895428));
#1532=CARTESIAN_POINT('',(51.3852215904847,-5.50770985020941,43.8976218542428));
#1533=CARTESIAN_POINT('',(51.4507404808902,-5.42854525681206,43.9076326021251));
#1534=CARTESIAN_POINT('',(51.5961976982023,-5.23951810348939,43.9297023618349));
#1535=CARTESIAN_POINT('',(51.6740256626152,-5.12794986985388,43.941389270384));
#1536=CARTESIAN_POINT('',(51.7808583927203,-4.95518253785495,43.9572018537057));
#1537=CARTESIAN_POINT('',(51.8146702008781,-4.89700096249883,43.9621654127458));
#1538=CARTESIAN_POINT('',(51.8786533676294,-4.77856487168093,43.9714583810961));
#1539=CARTESIAN_POINT('',(51.9088236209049,-4.71830973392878,43.97578759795));
#1540=CARTESIAN_POINT('',(51.9499833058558,-4.62790712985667,43.9815925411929));
#1541=CARTESIAN_POINT('',(51.9627234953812,-4.59857023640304,43.9833726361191));
#1542=CARTESIAN_POINT('',(51.9870435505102,-4.5394222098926,43.9867311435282));
#1543=CARTESIAN_POINT('',(51.9986240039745,-4.50961132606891,43.9883096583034));
#1544=CARTESIAN_POINT('',(52.0204427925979,-4.44952799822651,43.9912335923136));
#1545=CARTESIAN_POINT('',(52.0306826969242,-4.41925614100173,43.9925792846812));
#1546=CARTESIAN_POINT('',(52.0496954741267,-4.35787658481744,43.9950103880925));
#1547=CARTESIAN_POINT('',(52.058451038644,-4.32676336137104,43.9960927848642));
#1548=CARTESIAN_POINT('',(52.0740037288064,-4.263996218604,43.9979158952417));
#1549=CARTESIAN_POINT('',(52.0807990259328,-4.23234182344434,43.9986562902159));
#1550=CARTESIAN_POINT('',(52.0891056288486,-4.18444555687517,43.9994373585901));
#1551=CARTESIAN_POINT('',(52.0915638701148,-4.16837030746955,43.9996428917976));
#1552=CARTESIAN_POINT('',(52.0957334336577,-4.13611384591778,43.9999238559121));
#1553=CARTESIAN_POINT('',(52.0974443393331,-4.11993257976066,43.9999992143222));
#1554=CARTESIAN_POINT('',(52.098726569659,-4.10371057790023,44.));
#1555=B_SPLINE_CURVE_WITH_KNOTS('',3,(#1521,#1522,#1523,#1524,#1525,#1526,#1527,#1528,#1529,
#1530,#1531,#1532,#1533,#1534,#1535,#1536,#1537,#1538,#1539,#1540,#1541,#1542,#1543,#1544,#1545,
#1546,#1547,#1548,#1549,#1550,#1551,#1552,#1553,#1554),.UNSPECIFIED.,.F.,.F.,(4,2,2,2,2,2,2,2,2,
2,2,2,2,2,2,2,4),(0.,0.299232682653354,0.599190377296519,0.899439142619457,1.2094771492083,
1.51927462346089,1.82881694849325,2.23758638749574,2.43991907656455,2.64231302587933,
2.7383935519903,2.83442512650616,2.93034326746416,3.02731265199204,3.12437219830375,
3.17314647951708,3.22194791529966),.UNSPECIFIED.);
#1556=CARTESIAN_POINT('',(50.1652900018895,-6.55059837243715,43.7057234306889));
#1557=VERTEX_POINT('',#1556);
#1558=EDGE_CURVE('E174',#1557,#1516,#1555,.T.);
#1559=ORIENTED_EDGE('',*,*,#1558,.F.);
#1560=CARTESIAN_POINT('',(0.,0.,43.7057234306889));
#1561=DIRECTION('',(0.,0.,-1.));
#1562=DIRECTION('',(0.,1.,0.));
#1563=AXIS2_PLACEMENT_3D('',#1560,#1561,#1562);
#1564=CIRCLE('',#1563,50.5911717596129);
#1565=CARTESIAN_POINT('',(50.1652900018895,6.5505983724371,43.7057234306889));
#1566=VERTEX_POINT('',#1565);
#1567=EDGE_CURVE('E525',#1566,#1557,#1564,.F.);
#1568=ORIENTED_EDGE('',*,*,#1567,.F.);
#1569=CARTESIAN_POINT('',(52.098726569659,4.10371057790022,44.));
#1570=CARTESIAN_POINT('',(52.0973675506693,4.12089362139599,43.9999990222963));
#1571=CARTESIAN_POINT('',(52.0955287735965,4.13803041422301,43.9999145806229));
#1572=CARTESIAN_POINT('',(52.0910196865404,4.17218296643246,43.9996008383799));
#1573=CARTESIAN_POINT('',(52.0883499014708,4.1891987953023,43.9993716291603));
#1574=CARTESIAN_POINT('',(52.0793157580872,4.23986613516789,43.9985029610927));
#1575=CARTESIAN_POINT('',(52.0719086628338,4.27332869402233,43.9976819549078));
#1576=CARTESIAN_POINT('',(52.0549558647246,4.33964180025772,43.9956667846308));
#1577=CARTESIAN_POINT('',(52.0454124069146,4.3724929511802,43.9944730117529));
#1578=CARTESIAN_POINT('',(52.024700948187,4.43726050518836,43.9917973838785));
#1579=CARTESIAN_POINT('',(52.0135521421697,4.46918323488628,43.9903188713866));
#1580=CARTESIAN_POINT('',(51.98980691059,4.53251786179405,43.9871105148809));
#1581=CARTESIAN_POINT('',(51.9772085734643,4.56392902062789,43.9853803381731));
#1582=CARTESIAN_POINT('',(51.950760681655,4.62622825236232,43.9817025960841));
#1583=CARTESIAN_POINT('',(51.9369103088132,4.65711596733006,43.9797548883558));
#1584=CARTESIAN_POINT('',(51.8954609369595,4.74526979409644,43.9738735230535));
#1585=CARTESIAN_POINT('',(51.8664734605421,4.80187004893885,43.9696984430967));
#1586=CARTESIAN_POINT('',(51.8053069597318,4.91324882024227,43.9607925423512));
#1587=CARTESIAN_POINT('',(51.7731282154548,4.9680274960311,43.9560617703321));
#1588=CARTESIAN_POINT('',(51.7060071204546,5.07581814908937,43.946118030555));
#1589=CARTESIAN_POINT('',(51.6710645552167,5.12882998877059,43.9409050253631));
#1590=CARTESIAN_POINT('',(51.5799486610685,5.26019810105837,43.9272317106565));
#1591=CARTESIAN_POINT('',(51.5221742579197,5.33741790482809,43.918491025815));
#1592=CARTESIAN_POINT('',(51.4017759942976,5.48787589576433,43.9001530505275));
#1593=CARTESIAN_POINT('',(51.33915112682,5.56111325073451,43.8905555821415));
#1594=CARTESIAN_POINT('',(51.2195390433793,5.69268915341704,43.8721241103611));
#1595=CARTESIAN_POINT('',(51.1631546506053,5.7515931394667,43.8633978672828));
#1596=CARTESIAN_POINT('',(51.0475881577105,5.86652922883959,43.8454396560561));
#1597=CARTESIAN_POINT('',(50.9884055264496,5.92256078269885,43.8362075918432));
#1598=CARTESIAN_POINT('',(50.8674784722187,6.03173036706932,43.8172740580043));
#1599=CARTESIAN_POINT('',(50.8057334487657,6.08486771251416,43.8075724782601));
#1600=CARTESIAN_POINT('',(50.6816734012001,6.18675747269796,43.7880125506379));
#1601=CARTESIAN_POINT('',(50.6194231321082,6.23559114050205,43.7781662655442));
#1602=CARTESIAN_POINT('',(50.4929093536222,6.33044911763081,43.7580915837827));
#1603=CARTESIAN_POINT('',(50.4286464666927,6.37647428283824,43.7478633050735));
#1604=CARTESIAN_POINT('',(50.2983027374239,6.46567050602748,43.7270538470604));
#1605=CARTESIAN_POINT('',(50.2322234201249,6.50884386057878,43.716472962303));
#1606=CARTESIAN_POINT('',(50.1652900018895,6.55059837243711,43.7057234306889));
#1607=B_SPLINE_CURVE_WITH_KNOTS('',3,(#1569,#1570,#1571,#1572,#1573,#1574,#1575,#1576,#1577,
#1578,#1579,#1580,#1581,#1582,#1583,#1584,#1585,#1586,#1587,#1588,#1589,#1590,#1591,#1592,#1593,
#1594,#1595,#1596,#1597,#1598,#1599,#1600,#1601,#1602,#1603,#1604,#1605,#1606),.UNSPECIFIED.,
.F.,.F.,(4,2,2,2,2,2,2,2,2,2,2,2,2,2,2,2,2,2,4),(0.,0.0516905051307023,0.103348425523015,
0.206090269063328,0.308724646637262,0.410220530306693,0.511851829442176,0.613550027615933,
0.80459485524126,0.99562292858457,1.18666584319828,1.4769301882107,1.76725495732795,
2.01317295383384,2.25913781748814,2.50516065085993,2.74427124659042,2.98330860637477,
3.22215106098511),.UNSPECIFIED.);
#1608=CARTESIAN_POINT('',(52.0987265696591,4.10371057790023,44.));
#1609=VERTEX_POINT('',#1608);
#1610=EDGE_CURVE('E184',#1609,#1566,#1607,.T.);
#1611=ORIENTED_EDGE('',*,*,#1610,.F.);
#1612=CARTESIAN_POINT('',(51.9745338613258,5.45578414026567,44.));
#1613=VERTEX_POINT('',#1612);
#1614=EDGE_CURVE('E35',#1613,#1609,#1514,.F.);
#1615=ORIENTED_EDGE('',*,*,#1614,.F.);
#1616=EDGE_CURVE('E177',#1518,#1613,#1514,.F.);
#1617=ORIENTED_EDGE('',*,*,#1616,.F.);
#1618=EDGE_LOOP('',(#1520,#1559,#1568,#1611,#1615,#1617));
#1619=FACE_BOUND('',#1618,.T.);
#1620=ADVANCED_FACE('F171',(#1619),#1509,.F.);
#1621=CARTESIAN_POINT('',(0.,0.,39.3725693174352));
#1622=DIRECTION('',(0.,0.,-1.));
#1623=DIRECTION('',(0.,1.,0.));
#1624=AXIS2_PLACEMENT_3D('',#1621,#1622,#1623);
#1625=TOROIDAL_SURFACE('',#1624,51.3552237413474,4.4);
#1626=ORIENTED_EDGE('',*,*,#1469,.F.);
#1627=ORIENTED_EDGE('',*,*,#1395,.T.);
#1628=ORIENTED_EDGE('',*,*,#1495,.F.);
#1629=CARTESIAN_POINT('',(50.1652900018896,6.5505983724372,43.7057234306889));
#1630=CARTESIAN_POINT('',(50.1128968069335,6.58328785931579,43.6973060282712));
#1631=CARTESIAN_POINT('',(50.0606912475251,6.61607514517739,43.6881254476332));
#1632=CARTESIAN_POINT('',(49.9565620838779,6.68163418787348,43.6682130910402));
#1633=CARTESIAN_POINT('',(49.9046384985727,6.71440594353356,43.6574812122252));
#1634=CARTESIAN_POINT('',(49.748474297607,6.8128073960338,43.6227705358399));
#1635=CARTESIAN_POINT('',(49.6445322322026,6.87808437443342,43.59638747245));
#1636=CARTESIAN_POINT('',(49.4368595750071,7.00642470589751,43.5367986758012));
#1637=CARTESIAN_POINT('',(49.333130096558,7.06948234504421,43.5035766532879));
#1638=CARTESIAN_POINT('',(49.1270473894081,7.19148271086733,43.430165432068));
#1639=CARTESIAN_POINT('',(49.0246901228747,7.25045702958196,43.3900407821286));
#1640=CARTESIAN_POINT('',(48.8209549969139,7.36368178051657,43.302160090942));
#1641=CARTESIAN_POINT('',(48.7195754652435,7.41794242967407,43.2544212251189));
#1642=CARTESIAN_POINT('',(48.5183215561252,7.52069611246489,43.1507495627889));
#1643=CARTESIAN_POINT('',(48.4184447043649,7.56919981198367,43.0948323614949));
#1644=CARTESIAN_POINT('',(48.2656816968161,7.63891400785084,43.0015414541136));
#1645=CARTESIAN_POINT('',(48.2120076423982,7.66253368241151,42.967244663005));
#1646=CARTESIAN_POINT('',(48.1053895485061,7.7075578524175,42.8958707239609));
#1647=CARTESIAN_POINT('',(48.0524477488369,7.72895647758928,42.858786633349));
#1648=CARTESIAN_POINT('',(47.8556050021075,7.8046053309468,42.7142450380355));
#1649=CARTESIAN_POINT('',(47.7149547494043,7.85068114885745,42.5973898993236));
#1650=CARTESIAN_POINT('',(47.5147670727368,7.90119310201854,42.4064929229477));
#1651=CARTESIAN_POINT('',(47.4498803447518,7.91492678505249,42.3403135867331));
#1652=CARTESIAN_POINT('',(47.3244800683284,7.9354585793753,42.2029589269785));
#1653=CARTESIAN_POINT('',(47.2639618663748,7.94226417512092,42.1317890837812));
#1654=CARTESIAN_POINT('',(47.1732241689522,7.94688148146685,42.0166774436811));
#1655=CARTESIAN_POINT('',(47.141200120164,7.94730709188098,41.9742400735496));
#1656=CARTESIAN_POINT('',(47.0790330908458,7.94552389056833,41.888062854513));
#1657=CARTESIAN_POINT('',(47.0488901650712,7.94331500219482,41.8443229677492));
#1658=CARTESIAN_POINT('',(47.0197678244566,7.93971944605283,41.8));
#1659=B_SPLINE_CURVE_WITH_KNOTS('',3,(#1629,#1630,#1631,#1632,#1633,#1634,#1635,#1636,#1637,
#1638,#1639,#1640,#1641,#1642,#1643,#1644,#1645,#1646,#1647,#1648,#1649,#1650,#1651,#1652,#1653,
#1654,#1655,#1656,#1657,#1658),.UNSPECIFIED.,.F.,.F.,(4,2,2,2,2,2,2,2,2,2,2,2,2,2,4),(0.,
0.18696566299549,0.37394372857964,0.750377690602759,1.12771885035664,1.50170619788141,
1.87486157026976,2.24731443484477,2.45101826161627,2.6552474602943,3.21751515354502,
3.49822904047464,3.77863934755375,3.9380357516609,4.09743679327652),.UNSPECIFIED.);
#1660=EDGE_CURVE('E527',#1566,#1477,#1659,.T.);
#1661=ORIENTED_EDGE('',*,*,#1660,.F.);
#1662=ORIENTED_EDGE('',*,*,#1567,.T.);
#1663=CARTESIAN_POINT('',(47.0197678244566,-7.93971944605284,41.8));
#1664=CARTESIAN_POINT('',(47.0617598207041,-7.94490888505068,41.8639341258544));
#1665=CARTESIAN_POINT('',(47.1058914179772,-7.94720737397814,41.9266415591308));
#1666=CARTESIAN_POINT('',(47.1978546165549,-7.94645581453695,42.0491452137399));
#1667=CARTESIAN_POINT('',(47.2456819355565,-7.94341187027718,42.1089446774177));
#1668=CARTESIAN_POINT('',(47.3441897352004,-7.93245936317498,42.2248916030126));
#1669=CARTESIAN_POINT('',(47.3948464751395,-7.92458697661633,42.2810628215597));
#1670=CARTESIAN_POINT('',(47.4988347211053,-7.90444039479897,42.3900279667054));
#1671=CARTESIAN_POINT('',(47.5521664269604,-7.89216587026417,42.4428216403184));
#1672=CARTESIAN_POINT('',(47.6696184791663,-7.86137995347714,42.5529574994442));
#1673=CARTESIAN_POINT('',(47.7341161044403,-7.84219114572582,42.6097085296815));
#1674=CARTESIAN_POINT('',(47.8654340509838,-7.79907697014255,42.7184986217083));
#1675=CARTESIAN_POINT('',(47.9322549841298,-7.7751503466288,42.7705364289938));
#1676=CARTESIAN_POINT('',(48.1828805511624,-7.67882307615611,42.954543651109));
#1677=CARTESIAN_POINT('',(48.3724953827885,-7.59314949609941,43.0720518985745));
#1678=CARTESIAN_POINT('',(48.6609490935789,-7.44851148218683,43.2253583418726));
#1679=CARTESIAN_POINT('',(48.7581137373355,-7.3974068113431,43.2727575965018));
#1680=CARTESIAN_POINT('',(48.9532508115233,-7.29074688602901,43.3603500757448));
#1681=CARTESIAN_POINT('',(49.051222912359,-7.23519337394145,43.4005461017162));
#1682=CARTESIAN_POINT('',(49.2338529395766,-7.12863774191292,43.4690530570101));
#1683=CARTESIAN_POINT('',(49.3184535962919,-7.07808805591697,43.4982401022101));
#1684=CARTESIAN_POINT('',(49.4879534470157,-6.97503589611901,43.551948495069));
#1685=CARTESIAN_POINT('',(49.5728526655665,-6.92253325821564,43.5764694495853));
#1686=CARTESIAN_POINT('',(49.741980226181,-6.81693076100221,43.6208145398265));
#1687=CARTESIAN_POINT('',(49.8262040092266,-6.76384614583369,43.6406926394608));
#1688=CARTESIAN_POINT('',(49.9529709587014,-6.68391925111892,43.6673972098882));
#1689=CARTESIAN_POINT('',(49.9952903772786,-6.65723207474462,43.6757786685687));
#1690=CARTESIAN_POINT('',(50.0801281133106,-6.60387369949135,43.6915168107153));
#1691=CARTESIAN_POINT('',(50.1226464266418,-6.57720250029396,43.6988735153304));
#1692=CARTESIAN_POINT('',(50.1652900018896,-6.55059837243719,43.7057234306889));
#1693=B_SPLINE_CURVE_WITH_KNOTS('',3,(#1663,#1664,#1665,#1666,#1667,#1668,#1669,#1670,#1671,
#1672,#1673,#1674,#1675,#1676,#1677,#1678,#1679,#1680,#1681,#1682,#1683,#1684,#1685,#1686,#1687,
#1688,#1689,#1690,#1691,#1692),.UNSPECIFIED.,.F.,.F.,(4,2,2,2,2,2,2,2,2,2,2,2,2,2,4),(0.,
0.229839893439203,0.459417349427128,0.687295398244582,0.915190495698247,1.17894004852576,
1.44275959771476,2.15495168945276,2.51352494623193,2.87195844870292,3.18018586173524,
3.4884392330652,3.79290840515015,3.94508496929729,4.09725839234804),.UNSPECIFIED.);
#1694=EDGE_CURVE('E183',#1468,#1557,#1693,.T.);
#1695=ORIENTED_EDGE('',*,*,#1694,.F.);
#1696=EDGE_LOOP('',(#1626,#1627,#1628,#1661,#1662,#1695));
#1697=FACE_BOUND('',#1696,.T.);
#1698=ADVANCED_FACE('F208',(#1697),#1625,.T.);
#1699=CARTESIAN_POINT('',(48.,0.,41.8));
#1700=DIRECTION('',(0.,0.,-1.));
#1701=DIRECTION('',(0.,1.,0.));
#1702=AXIS2_PLACEMENT_3D('',#1699,#1700,#1701);
#1703=TOROIDAL_SURFACE('',#1702,5.8,2.2);
#1704=ORIENTED_EDGE('',*,*,#1694,.T.);
#1705=ORIENTED_EDGE('',*,*,#1558,.T.);
#1706=CARTESIAN_POINT('',(48.,0.,44.));
#1707=DIRECTION('',(0.,0.,-1.));
#1708=DIRECTION('',(0.706676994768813,-0.707536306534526,0.));
#1709=AXIS2_PLACEMENT_3D('',#1706,#1707,#1708);
#1710=CIRCLE('',#1709,5.79999999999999);
#1711=CARTESIAN_POINT('',(48.0000000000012,-5.8,44.));
#1712=VERTEX_POINT('',#1711);
#1713=EDGE_CURVE('E157',#1712,#1516,#1710,.F.);
#1714=ORIENTED_EDGE('',*,*,#1713,.F.);
#1715=CARTESIAN_POINT('',(48.,0.,44.));
#1716=DIRECTION('',(0.,0.,-1.));
#1717=DIRECTION('',(5.27595208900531E-13,-1.,0.));
#1718=AXIS2_PLACEMENT_3D('',#1715,#1716,#1717);
#1719=CIRCLE('',#1718,5.80000000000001);
#1720=CARTESIAN_POINT('',(48.,5.8,44.));
#1721=VERTEX_POINT('',#1720);
#1722=EDGE_CURVE('E163',#1712,#1721,#1719,.T.);
#1723=ORIENTED_EDGE('',*,*,#1722,.T.);
#1724=CARTESIAN_POINT('',(48.,0.,44.));
#1725=DIRECTION('',(0.,0.,-1.));
#1726=DIRECTION('',(0.,1.,0.));
#1727=AXIS2_PLACEMENT_3D('',#1724,#1725,#1726);
#1728=CIRCLE('',#1727,5.80000000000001);
#1729=EDGE_CURVE('E124',#1609,#1721,#1728,.F.);
#1730=ORIENTED_EDGE('',*,*,#1729,.F.);
#1731=ORIENTED_EDGE('',*,*,#1610,.T.);
#1732=ORIENTED_EDGE('',*,*,#1660,.T.);
#1733=ORIENTED_EDGE('',*,*,#1478,.F.);
#1734=EDGE_LOOP('',(#1704,#1705,#1714,#1723,#1730,#1731,#1732,#1733));
#1735=FACE_BOUND('',#1734,.T.);
#1736=ADVANCED_FACE('F180',(#1735),#1703,.T.);
#1737=CARTESIAN_POINT('',(-55.3035084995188,0.,44.));
#1738=DIRECTION('',(0.,0.,1.));
#1739=DIRECTION('',(0.,-1.,0.));
#1740=AXIS2_PLACEMENT_3D('',#1737,#1738,#1739);
#1741=PLANE('',#1740);
#1742=CARTESIAN_POINT('',(48.,0.,44.));
#1743=DIRECTION('',(0.,0.,1.));
#1744=DIRECTION('',(0.,-1.,0.));
#1745=AXIS2_PLACEMENT_3D('',#1742,#1743,#1744);
#1746=CIRCLE('',#1745,6.75);
#1747=EDGE_CURVE('E9',#1518,#1613,#1746,.T.);
#1748=ORIENTED_EDGE('',*,*,#1747,.F.);
#1749=ORIENTED_EDGE('',*,*,#1616,.T.);
#1750=EDGE_LOOP('',(#1748,#1749));
#1751=FACE_BOUND('',#1750,.T.);
#1752=ORIENTED_EDGE('',*,*,#1426,.F.);
#1753=ORIENTED_EDGE('',*,*,#1442,.F.);
#1754=ORIENTED_EDGE('',*,*,#1435,.F.);
#1755=EDGE_LOOP('',(#1752,#1753,#1754));
#1756=FACE_BOUND('',#1755,.T.);
#1757=ADVANCED_FACE('F510',(#1751,#1756),#1741,.T.);
#1758=CARTESIAN_POINT('',(-49.5331616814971,0.,22.));
#1759=DIRECTION('',(0.,0.,-1.));
#1760=DIRECTION('',(0.,1.,0.));
#1761=AXIS2_PLACEMENT_3D('',#1758,#1759,#1760);
#1762=PLANE('',#1761);
#1763=ORIENTED_EDGE('',*,*,#230,.T.);
#1764=ORIENTED_EDGE('',*,*,#246,.T.);
#1765=ORIENTED_EDGE('',*,*,#239,.T.);
#1766=EDGE_LOOP('',(#1763,#1764,#1765));
#1767=FACE_BOUND('',#1766,.T.);
#1768=ORIENTED_EDGE('',*,*,#434,.T.);
#1769=ORIENTED_EDGE('',*,*,#459,.T.);
#1770=CARTESIAN_POINT('',(48.,0.,22.));
#1771=DIRECTION('',(0.,0.,1.));
#1772=DIRECTION('',(0.,-1.,0.));
#1773=AXIS2_PLACEMENT_3D('',#1770,#1771,#1772);
#1774=CIRCLE('',#1773,5.33333333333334);
#1775=EDGE_CURVE('E485',#451,#442,#1774,.T.);
#1776=ORIENTED_EDGE('',*,*,#1775,.T.);
#1777=ORIENTED_EDGE('',*,*,#443,.T.);
#1778=EDGE_LOOP('',(#1768,#1769,#1776,#1777));
#1779=FACE_BOUND('',#1778,.T.);
#1780=ADVANCED_FACE('F260',(#1767,#1779),#1762,.T.);
#1781=CARTESIAN_POINT('',(45.3333333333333,0.,22.));
#1782=DIRECTION('',(0.,0.,-1.));
#1783=DIRECTION('',(0.,1.,0.));
#1784=AXIS2_PLACEMENT_3D('',#1781,#1782,#1783);
#1785=PLANE('',#1784);
#1786=CARTESIAN_POINT('',(48.,0.,22.));
#1787=DIRECTION('',(0.,0.,1.));
#1788=DIRECTION('',(0.,-1.,0.));
#1789=AXIS2_PLACEMENT_3D('',#1786,#1787,#1788);
#1790=CIRCLE('',#1789,5.33333333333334);
#1791=EDGE_CURVE('E1500',#442,#451,#1790,.T.);
#1792=ORIENTED_EDGE('',*,*,#1791,.T.);
#1793=ORIENTED_EDGE('',*,*,#452,.T.);
#1794=EDGE_LOOP('',(#1792,#1793));
#1795=FACE_BOUND('',#1794,.T.);
#1796=ADVANCED_FACE('F371',(#1795),#1785,.F.);
#1797=CARTESIAN_POINT('',(48.,0.,23.8333333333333));
#1798=DIRECTION('',(0.,0.,1.));
#1799=DIRECTION('',(0.,-1.,0.));
#1800=AXIS2_PLACEMENT_3D('',#1797,#1798,#1799);
#1801=CYLINDRICAL_SURFACE('',#1800,5.33333333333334);
#1802=ORIENTED_EDGE('',*,*,#1791,.F.);
#1803=ORIENTED_EDGE('',*,*,#1775,.F.);
#1804=EDGE_LOOP('',(#1802,#1803));
#1805=FACE_BOUND('',#1804,.T.);
#1806=CARTESIAN_POINT('',(48.,0.,25.6666666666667));
#1807=DIRECTION('',(0.,0.,1.));
#1808=DIRECTION('',(0.,-1.,0.));
#1809=AXIS2_PLACEMENT_3D('',#1806,#1807,#1808);
#1810=CIRCLE('',#1809,5.33333333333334);
#1811=CARTESIAN_POINT('',(48.,-5.33333333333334,25.6666666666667));
#1812=VERTEX_POINT('',#1811);
#1813=EDGE_CURVE('E458',#1812,#1812,#1810,.F.);
#1814=ORIENTED_EDGE('',*,*,#1813,.F.);
#1815=EDGE_LOOP('',(#1814));
#1816=FACE_BOUND('',#1815,.T.);
#1817=ADVANCED_FACE('F338',(#1805,#1816),#1801,.F.);
#1818=CARTESIAN_POINT('',(43.3333333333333,0.,25.6666666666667));
#1819=DIRECTION('',(0.,0.,1.));
#1820=DIRECTION('',(0.,-1.,0.));
#1821=AXIS2_PLACEMENT_3D('',#1818,#1819,#1820);
#1822=PLANE('',#1821);
#1823=CARTESIAN_POINT('',(48.,0.,25.666666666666));
#1824=DIRECTION('',(0.,0.,-1.));
#1825=DIRECTION('',(0.,1.,0.));
#1826=AXIS2_PLACEMENT_3D('',#1823,#1824,#1825);
#1827=CIRCLE('',#1826,4.00000000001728);
#1828=CARTESIAN_POINT('',(48.,4.00000000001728,25.666666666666));
#1829=VERTEX_POINT('',#1828);
#1830=EDGE_CURVE('E918',#1829,#1829,#1827,.T.);
#1831=ORIENTED_EDGE('',*,*,#1830,.F.);
#1832=EDGE_LOOP('',(#1831));
#1833=FACE_BOUND('',#1832,.T.);
#1834=ORIENTED_EDGE('',*,*,#1813,.T.);
#1835=EDGE_LOOP('',(#1834));
#1836=FACE_BOUND('',#1835,.T.);
#1837=ADVANCED_FACE('F1162',(#1833,#1836),#1822,.F.);
#1838=CARTESIAN_POINT('',(48.,0.,25.6666666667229));
#1839=DIRECTION('',(0.,0.,-1.));
#1840=DIRECTION('',(0.,1.,0.));
#1841=AXIS2_PLACEMENT_3D('',#1838,#1839,#1840);
#1842=CONICAL_SURFACE('',#1841,3.99999999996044,0.785398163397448);
#1843=ORIENTED_EDGE('',*,*,#1830,.T.);
#1844=EDGE_LOOP('',(#1843));
#1845=FACE_BOUND('',#1844,.T.);
#1846=CARTESIAN_POINT('',(48.,0.,26.3431666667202));
#1847=DIRECTION('',(0.,0.,-1.));
#1848=DIRECTION('',(-1.,0.,0.));
#1849=AXIS2_PLACEMENT_3D('',#1846,#1847,#1848);
#1850=CIRCLE('',#1849,3.32349999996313);
#1851=CARTESIAN_POINT('',(44.6765000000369,0.,26.3431666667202));
#1852=VERTEX_POINT('',#1851);
#1853=EDGE_CURVE('E607',#1852,#1852,#1850,.T.);
#1854=ORIENTED_EDGE('',*,*,#1853,.F.);
#1855=EDGE_LOOP('',(#1854));
#1856=FACE_BOUND('',#1855,.T.);
#1857=ADVANCED_FACE('F1154',(#1845,#1856),#1842,.F.);
#1858=CARTESIAN_POINT('',(48.,0.,34.8333333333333));
#1859=DIRECTION('',(0.,0.,1.));
#1860=DIRECTION('',(0.,-1.,0.));
#1861=AXIS2_PLACEMENT_3D('',#1858,#1859,#1860);
#1862=CYLINDRICAL_SURFACE('',#1861,3.3235);
#1863=CARTESIAN_POINT('',(48.,0.,29.0904999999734));
#1864=DIRECTION('',(0.,0.,1.));
#1865=DIRECTION('',(0.,-1.,0.));
#1866=AXIS2_PLACEMENT_3D('',#1863,#1864,#1865);
#1867=CIRCLE('',#1866,3.3235);
#1868=CARTESIAN_POINT('',(48.,-3.32349999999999,29.0904999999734));
#1869=VERTEX_POINT('',#1868);
#1870=EDGE_CURVE('E26',#1869,#1869,#1867,.T.);
#1871=ORIENTED_EDGE('',*,*,#1870,.T.);
#1872=EDGE_LOOP('',(#1871));
#1873=FACE_BOUND('',#1872,.T.);
#1874=ORIENTED_EDGE('',*,*,#1853,.T.);
#1875=EDGE_LOOP('',(#1874));
#1876=FACE_BOUND('',#1875,.T.);
#1877=ADVANCED_FACE('F598',(#1873,#1876),#1862,.F.);
#1878=CARTESIAN_POINT('',(48.,0.,98.));
#1879=DIRECTION('',(0.,0.,1.));
#1880=DIRECTION('',(0.,1.,0.));
#1881=AXIS2_PLACEMENT_3D('',#1878,#1879,#1880);
#1882=SPHERICAL_SURFACE('',#1881,11.);
#1883=CARTESIAN_POINT('',(48.,0.,109.));
#1884=VERTEX_POINT('',#1883);
#1885=VERTEX_LOOP('',#1884);
#1886=FACE_BOUND('',#1885,.T.);
#1887=CARTESIAN_POINT('',(48.,0.,98.));
#1888=DIRECTION('',(0.,0.,1.));
#1889=DIRECTION('',(0.,-1.,0.));
#1890=AXIS2_PLACEMENT_3D('',#1887,#1888,#1889);
#1891=CIRCLE('',#1890,11.);
#1892=CARTESIAN_POINT('',(48.,-11.,98.));
#1893=VERTEX_POINT('',#1892);
#1894=EDGE_CURVE('E1551',#1893,#1893,#1891,.F.);
#1895=ORIENTED_EDGE('',*,*,#1894,.F.);
#1896=EDGE_LOOP('',(#1895));
#1897=FACE_BOUND('',#1896,.T.);
#1898=ADVANCED_FACE('F793',(#1886,#1897),#1882,.T.);
#1899=CARTESIAN_POINT('',(48.,0.,82.5));
#1900=DIRECTION('',(0.,0.,1.));
#1901=DIRECTION('',(0.,-1.,0.));
#1902=AXIS2_PLACEMENT_3D('',#1899,#1900,#1901);
#1903=CYLINDRICAL_SURFACE('',#1902,11.);
#1904=ORIENTED_EDGE('',*,*,#1894,.T.);
#1905=EDGE_LOOP('',(#1904));
#1906=FACE_BOUND('',#1905,.T.);
#1907=CARTESIAN_POINT('',(48.,0.,67.));
#1908=DIRECTION('',(0.,0.,1.));
#1909=DIRECTION('',(0.,-1.,0.));
#1910=AXIS2_PLACEMENT_3D('',#1907,#1908,#1909);
#1911=CIRCLE('',#1910,11.);
#1912=CARTESIAN_POINT('',(48.,-11.,67.));
#1913=VERTEX_POINT('',#1912);
#1914=EDGE_CURVE('E231',#1913,#1913,#1911,.T.);
#1915=ORIENTED_EDGE('',*,*,#1914,.T.);
#1916=EDGE_LOOP('',(#1915));
#1917=FACE_BOUND('',#1916,.T.);
#1918=ADVANCED_FACE('F140',(#1906,#1917),#1903,.T.);
#1919=CARTESIAN_POINT('',(48.,0.,67.));
#1920=DIRECTION('',(0.,0.,-1.));
#1921=DIRECTION('',(-1.,0.,0.));
#1922=AXIS2_PLACEMENT_3D('',#1919,#1920,#1921);
#1923=TOROIDAL_SURFACE('',#1922,9.,2.);
#1924=ORIENTED_EDGE('',*,*,#1914,.F.);
#1925=EDGE_LOOP('',(#1924));
#1926=FACE_BOUND('',#1925,.T.);
#1927=CARTESIAN_POINT('',(48.,0.,65.));
#1928=DIRECTION('',(0.,0.,-1.));
#1929=DIRECTION('',(-1.,0.,0.));
#1930=AXIS2_PLACEMENT_3D('',#1927,#1928,#1929);
#1931=CIRCLE('',#1930,9.);
#1932=CARTESIAN_POINT('',(39.,0.,65.));
#1933=VERTEX_POINT('',#1932);
#1934=EDGE_CURVE('E107',#1933,#1933,#1931,.F.);
#1935=ORIENTED_EDGE('',*,*,#1934,.T.);
#1936=EDGE_LOOP('',(#1935));
#1937=FACE_BOUND('',#1936,.T.);
#1938=ADVANCED_FACE('F787',(#1926,#1937),#1923,.T.);
#1939=CARTESIAN_POINT('',(48.,0.,54.65));
#1940=DIRECTION('',(0.,0.,1.));
#1941=DIRECTION('',(0.,-1.,0.));
#1942=AXIS2_PLACEMENT_3D('',#1939,#1940,#1941);
#1943=CYLINDRICAL_SURFACE('',#1942,9.);
#1944=CARTESIAN_POINT('',(48.,0.,44.3));
#1945=DIRECTION('',(0.,0.,1.));
#1946=DIRECTION('',(0.,-1.,0.));
#1947=AXIS2_PLACEMENT_3D('',#1944,#1945,#1946);
#1948=CIRCLE('',#1947,9.);
#1949=CARTESIAN_POINT('',(48.,-8.99999999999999,44.3));
#1950=VERTEX_POINT('',#1949);
#1951=EDGE_CURVE('E104',#1950,#1950,#1948,.T.);
#1952=ORIENTED_EDGE('',*,*,#1951,.T.);
#1953=EDGE_LOOP('',(#1952));
#1954=FACE_BOUND('',#1953,.T.);
#1955=ORIENTED_EDGE('',*,*,#1934,.F.);
#1956=EDGE_LOOP('',(#1955));
#1957=FACE_BOUND('',#1956,.T.);
#1958=ADVANCED_FACE('F791',(#1954,#1957),#1943,.T.);
#1959=CARTESIAN_POINT('',(48.,7.875,44.3));
#1960=DIRECTION('',(0.,0.,-1.));
#1961=DIRECTION('',(0.,1.,0.));
#1962=AXIS2_PLACEMENT_3D('',#1959,#1960,#1961);
#1963=PLANE('',#1962);
#1964=ORIENTED_EDGE('',*,*,#1951,.F.);
#1965=EDGE_LOOP('',(#1964));
#1966=FACE_BOUND('',#1965,.T.);
#1967=CARTESIAN_POINT('',(48.,0.,44.3));
#1968=DIRECTION('',(0.,0.,1.));
#1969=DIRECTION('',(0.,-1.,0.));
#1970=AXIS2_PLACEMENT_3D('',#1967,#1968,#1969);
#1971=CIRCLE('',#1970,6.75);
#1972=CARTESIAN_POINT('',(48.,-6.74999999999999,44.3));
#1973=VERTEX_POINT('',#1972);
#1974=EDGE_CURVE('E108',#1973,#1973,#1971,.T.);
#1975=ORIENTED_EDGE('',*,*,#1974,.T.);
#1976=EDGE_LOOP('',(#1975));
#1977=FACE_BOUND('',#1976,.T.);
#1978=ADVANCED_FACE('F799',(#1966,#1977),#1963,.T.);
#1979=CARTESIAN_POINT('',(48.,0.,44.15));
#1980=DIRECTION('',(0.,0.,1.));
#1981=DIRECTION('',(0.,-1.,0.));
#1982=AXIS2_PLACEMENT_3D('',#1979,#1980,#1981);
#1983=CYLINDRICAL_SURFACE('',#1982,6.75);
#1984=ORIENTED_EDGE('',*,*,#1747,.T.);
#1985=CARTESIAN_POINT('',(48.,0.,44.));
#1986=DIRECTION('',(0.,0.,1.));
#1987=DIRECTION('',(0.,-1.,0.));
#1988=AXIS2_PLACEMENT_3D('',#1985,#1986,#1987);
#1989=CIRCLE('',#1988,6.75);
#1990=EDGE_CURVE('E111',#1613,#1518,#1989,.T.);
#1991=ORIENTED_EDGE('',*,*,#1990,.T.);
#1992=EDGE_LOOP('',(#1984,#1991));
#1993=FACE_BOUND('',#1992,.T.);
#1994=ORIENTED_EDGE('',*,*,#1974,.F.);
#1995=EDGE_LOOP('',(#1994));
#1996=FACE_BOUND('',#1995,.T.);
#1997=ADVANCED_FACE('F139',(#1993,#1996),#1983,.T.);
#1998=CARTESIAN_POINT('',(48.,4.9915,44.));
#1999=DIRECTION('',(0.,0.,-1.));
#2000=DIRECTION('',(0.,1.,0.));
#2001=AXIS2_PLACEMENT_3D('',#1998,#1999,#2000);
#2002=PLANE('',#2001);
#2003=ORIENTED_EDGE('',*,*,#1519,.T.);
#2004=ORIENTED_EDGE('',*,*,#1990,.F.);
#2005=ORIENTED_EDGE('',*,*,#1614,.T.);
#2006=ORIENTED_EDGE('',*,*,#1729,.T.);
#2007=ORIENTED_EDGE('',*,*,#1722,.F.);
#2008=ORIENTED_EDGE('',*,*,#1713,.T.);
#2009=EDGE_LOOP('',(#2003,#2004,#2005,#2006,#2007,#2008));
#2010=FACE_BOUND('',#2009,.T.);
#2011=ADVANCED_FACE('F129',(#2010),#2002,.T.);
#2012=CARTESIAN_POINT('',(48.,0.,33.));
#2013=DIRECTION('',(0.,0.,1.));
#2014=DIRECTION('',(0.,-1.,0.));
#2015=AXIS2_PLACEMENT_3D('',#2012,#2013,#2014);
#2016=PLANE('',#2015);
#2017=DIRECTION('',(-0.866025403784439,0.5,0.));
#2018=VECTOR('',#2017,1.);
#2019=CARTESIAN_POINT('',(48.,2.30940107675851,33.));
#2020=LINE('',#2019,#2018);
#2021=CARTESIAN_POINT('',(48.,2.30940107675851,33.));
#2022=VERTEX_POINT('',#2021);
#2023=CARTESIAN_POINT('',(50.,1.15470053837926,33.));
#2024=VERTEX_POINT('',#2023);
#2025=EDGE_CURVE('E1032',#2022,#2024,#2020,.F.);
#2026=ORIENTED_EDGE('',*,*,#2025,.T.);
#2027=DIRECTION('',(0.,1.,0.));
#2028=VECTOR('',#2027,1.);
#2029=CARTESIAN_POINT('',(50.,1.15470053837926,33.));
#2030=LINE('',#2029,#2028);
#2031=CARTESIAN_POINT('',(50.,-1.15470053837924,33.));
#2032=VERTEX_POINT('',#2031);
#2033=EDGE_CURVE('E1037',#2024,#2032,#2030,.F.);
#2034=ORIENTED_EDGE('',*,*,#2033,.T.);
#2035=DIRECTION('',(0.866025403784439,0.5,0.));
#2036=VECTOR('',#2035,1.);
#2037=CARTESIAN_POINT('',(50.,-1.15470053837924,33.));
#2038=LINE('',#2037,#2036);
#2039=CARTESIAN_POINT('',(48.,-2.30940107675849,33.));
#2040=VERTEX_POINT('',#2039);
#2041=EDGE_CURVE('E1042',#2032,#2040,#2038,.F.);
#2042=ORIENTED_EDGE('',*,*,#2041,.T.);
#2043=DIRECTION('',(0.866025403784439,-0.5,0.));
#2044=VECTOR('',#2043,1.);
#2045=CARTESIAN_POINT('',(48.,-2.30940107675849,33.));
#2046=LINE('',#2045,#2044);
#2047=CARTESIAN_POINT('',(46.,-1.15470053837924,33.));
#2048=VERTEX_POINT('',#2047);
#2049=EDGE_CURVE('E92',#2040,#2048,#2046,.F.);
#2050=ORIENTED_EDGE('',*,*,#2049,.T.);
#2051=DIRECTION('',(0.,-1.,0.));
#2052=VECTOR('',#2051,1.);
#2053=CARTESIAN_POINT('',(46.,-1.15470053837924,33.));
#2054=LINE('',#2053,#2052);
#2055=CARTESIAN_POINT('',(46.,1.15470053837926,33.));
#2056=VERTEX_POINT('',#2055);
#2057=EDGE_CURVE('E90',#2048,#2056,#2054,.F.);
#2058=ORIENTED_EDGE('',*,*,#2057,.T.);
#2059=DIRECTION('',(-0.866025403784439,-0.5,0.));
#2060=VECTOR('',#2059,1.);
#2061=CARTESIAN_POINT('',(46.,1.15470053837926,33.));
#2062=LINE('',#2061,#2060);
#2063=EDGE_CURVE('E77',#2056,#2022,#2062,.F.);
#2064=ORIENTED_EDGE('',*,*,#2063,.T.);
#2065=EDGE_LOOP('',(#2026,#2034,#2042,#2050,#2058,#2064));
#2066=FACE_BOUND('',#2065,.T.);
#2067=ADVANCED_FACE('F16',(#2066),#2016,.F.);
#2068=CARTESIAN_POINT('',(50.,-1.15470053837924,29.));
#2069=DIRECTION('',(0.5,-0.866025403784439,0.));
#2070=DIRECTION('',(0.866025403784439,0.5,0.));
#2071=AXIS2_PLACEMENT_3D('',#2068,#2069,#2070);
#2072=PLANE('',#2071);
#2073=DIRECTION('',(0.,0.,1.));
#2074=VECTOR('',#2073,1.);
#2075=CARTESIAN_POINT('',(50.,-1.15470053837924,29.));
#2076=LINE('',#2075,#2074);
#2077=CARTESIAN_POINT('',(50.,-1.15470053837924,29.));
#2078=VERTEX_POINT('',#2077);
#2079=EDGE_CURVE('E1040',#2032,#2078,#2076,.F.);
#2080=ORIENTED_EDGE('',*,*,#2079,.T.);
#2081=DIRECTION('',(0.866025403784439,0.5,0.));
#2082=VECTOR('',#2081,1.);
#2083=CARTESIAN_POINT('',(48.,-2.30940107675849,29.));
#2084=LINE('',#2083,#2082);
#2085=CARTESIAN_POINT('',(48.,-2.30940107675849,29.));
#2086=VERTEX_POINT('',#2085);
#2087=EDGE_CURVE('E1019',#2086,#2078,#2084,.T.);
#2088=ORIENTED_EDGE('',*,*,#2087,.F.);
#2089=DIRECTION('',(0.,0.,1.));
#2090=VECTOR('',#2089,1.);
#2091=CARTESIAN_POINT('',(48.,-2.30940107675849,29.));
#2092=LINE('',#2091,#2090);
#2093=EDGE_CURVE('E1044',#2040,#2086,#2092,.F.);
#2094=ORIENTED_EDGE('',*,*,#2093,.F.);
#2095=ORIENTED_EDGE('',*,*,#2041,.F.);
#2096=EDGE_LOOP('',(#2080,#2088,#2094,#2095));
#2097=FACE_BOUND('',#2096,.T.);
#2098=ADVANCED_FACE('F1053',(#2097),#2072,.F.);
#2099=CARTESIAN_POINT('',(48.,-2.30940107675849,29.));
#2100=DIRECTION('',(-0.5,-0.866025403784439,0.));
#2101=DIRECTION('',(0.866025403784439,-0.5,0.));
#2102=AXIS2_PLACEMENT_3D('',#2099,#2100,#2101);
#2103=PLANE('',#2102);
#2104=ORIENTED_EDGE('',*,*,#2093,.T.);
#2105=DIRECTION('',(0.866025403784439,-0.5,0.));
#2106=VECTOR('',#2105,1.);
#2107=CARTESIAN_POINT('',(46.,-1.15470053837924,29.));
#2108=LINE('',#2107,#2106);
#2109=CARTESIAN_POINT('',(46.,-1.15470053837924,29.));
#2110=VERTEX_POINT('',#2109);
#2111=EDGE_CURVE('E1024',#2110,#2086,#2108,.T.);
#2112=ORIENTED_EDGE('',*,*,#2111,.F.);
#2113=DIRECTION('',(0.,0.,1.));
#2114=VECTOR('',#2113,1.);
#2115=CARTESIAN_POINT('',(46.,-1.15470053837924,29.));
#2116=LINE('',#2115,#2114);
#2117=EDGE_CURVE('E95',#2048,#2110,#2116,.F.);
#2118=ORIENTED_EDGE('',*,*,#2117,.F.);
#2119=ORIENTED_EDGE('',*,*,#2049,.F.);
#2120=EDGE_LOOP('',(#2104,#2112,#2118,#2119));
#2121=FACE_BOUND('',#2120,.T.);
#2122=ADVANCED_FACE('F1048',(#2121),#2103,.F.);
#2123=CARTESIAN_POINT('',(46.,-1.15470053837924,29.));
#2124=DIRECTION('',(-1.,0.,0.));
#2125=DIRECTION('',(0.,-1.,0.));
#2126=AXIS2_PLACEMENT_3D('',#2123,#2124,#2125);
#2127=PLANE('',#2126);
#2128=ORIENTED_EDGE('',*,*,#2117,.T.);
#2129=DIRECTION('',(0.,1.,0.));
#2130=VECTOR('',#2129,1.);
#2131=CARTESIAN_POINT('',(46.,1.6165,29.));
#2132=LINE('',#2131,#2130);
#2133=CARTESIAN_POINT('',(46.,1.15470053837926,29.));
#2134=VERTEX_POINT('',#2133);
#2135=EDGE_CURVE('E99',#2134,#2110,#2132,.F.);
#2136=ORIENTED_EDGE('',*,*,#2135,.F.);
#2137=DIRECTION('',(0.,0.,1.));
#2138=VECTOR('',#2137,1.);
#2139=CARTESIAN_POINT('',(46.,1.15470053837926,29.));
#2140=LINE('',#2139,#2138);
#2141=EDGE_CURVE('E81',#2056,#2134,#2140,.F.);
#2142=ORIENTED_EDGE('',*,*,#2141,.F.);
#2143=ORIENTED_EDGE('',*,*,#2057,.F.);
#2144=EDGE_LOOP('',(#2128,#2136,#2142,#2143));
#2145=FACE_BOUND('',#2144,.T.);
#2146=ADVANCED_FACE('F97',(#2145),#2127,.F.);
#2147=CARTESIAN_POINT('',(46.,1.15470053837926,29.));
#2148=DIRECTION('',(-0.5,0.866025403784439,0.));
#2149=DIRECTION('',(-0.866025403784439,-0.5,0.));
#2150=AXIS2_PLACEMENT_3D('',#2147,#2148,#2149);
#2151=PLANE('',#2150);
#2152=ORIENTED_EDGE('',*,*,#2141,.T.);
#2153=DIRECTION('',(-0.866025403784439,-0.5,0.));
#2154=VECTOR('',#2153,1.);
#2155=CARTESIAN_POINT('',(48.,2.30940107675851,29.));
#2156=LINE('',#2155,#2154);
#2157=CARTESIAN_POINT('',(48.,2.30940107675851,29.));
#2158=VERTEX_POINT('',#2157);
#2159=EDGE_CURVE('E1030',#2158,#2134,#2156,.T.);
#2160=ORIENTED_EDGE('',*,*,#2159,.F.);
#2161=DIRECTION('',(0.,0.,1.));
#2162=VECTOR('',#2161,1.);
#2163=CARTESIAN_POINT('',(48.,2.30940107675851,29.));
#2164=LINE('',#2163,#2162);
#2165=EDGE_CURVE('E84',#2158,#2022,#2164,.T.);
#2166=ORIENTED_EDGE('',*,*,#2165,.T.);
#2167=ORIENTED_EDGE('',*,*,#2063,.F.);
#2168=EDGE_LOOP('',(#2152,#2160,#2166,#2167));
#2169=FACE_BOUND('',#2168,.T.);
#2170=ADVANCED_FACE('F79',(#2169),#2151,.F.);
#2171=CARTESIAN_POINT('',(48.,2.30940107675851,29.));
#2172=DIRECTION('',(0.5,0.866025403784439,0.));
#2173=DIRECTION('',(-0.866025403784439,0.5,0.));
#2174=AXIS2_PLACEMENT_3D('',#2171,#2172,#2173);
#2175=PLANE('',#2174);
#2176=ORIENTED_EDGE('',*,*,#2165,.F.);
#2177=DIRECTION('',(-0.866025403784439,0.5,0.));
#2178=VECTOR('',#2177,1.);
#2179=CARTESIAN_POINT('',(50.,1.15470053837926,29.));
#2180=LINE('',#2179,#2178);
#2181=CARTESIAN_POINT('',(50.,1.15470053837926,29.));
#2182=VERTEX_POINT('',#2181);
#2183=EDGE_CURVE('E117',#2182,#2158,#2180,.T.);
#2184=ORIENTED_EDGE('',*,*,#2183,.F.);
#2185=DIRECTION('',(0.,0.,1.));
#2186=VECTOR('',#2185,1.);
#2187=CARTESIAN_POINT('',(50.,1.15470053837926,29.));
#2188=LINE('',#2187,#2186);
#2189=EDGE_CURVE('E1035',#2024,#2182,#2188,.F.);
#2190=ORIENTED_EDGE('',*,*,#2189,.F.);
#2191=ORIENTED_EDGE('',*,*,#2025,.F.);
#2192=EDGE_LOOP('',(#2176,#2184,#2190,#2191));
#2193=FACE_BOUND('',#2192,.T.);
#2194=ADVANCED_FACE('F1008',(#2193),#2175,.F.);
#2195=CARTESIAN_POINT('',(50.,1.15470053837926,29.));
#2196=DIRECTION('',(1.,0.,0.));
#2197=DIRECTION('',(0.,1.,0.));
#2198=AXIS2_PLACEMENT_3D('',#2195,#2196,#2197);
#2199=PLANE('',#2198);
#2200=ORIENTED_EDGE('',*,*,#2189,.T.);
#2201=DIRECTION('',(0.,1.,0.));
#2202=VECTOR('',#2201,1.);
#2203=CARTESIAN_POINT('',(50.,1.6165,29.));
#2204=LINE('',#2203,#2202);
#2205=EDGE_CURVE('E1015',#2078,#2182,#2204,.T.);
#2206=ORIENTED_EDGE('',*,*,#2205,.F.);
#2207=ORIENTED_EDGE('',*,*,#2079,.F.);
#2208=ORIENTED_EDGE('',*,*,#2033,.F.);
#2209=EDGE_LOOP('',(#2200,#2206,#2207,#2208));
#2210=FACE_BOUND('',#2209,.T.);
#2211=ADVANCED_FACE('F1006',(#2210),#2199,.F.);
#2212=CARTESIAN_POINT('',(48.,1.6165,29.));
#2213=DIRECTION('',(0.,0.,-1.));
#2214=DIRECTION('',(0.,1.,0.));
#2215=AXIS2_PLACEMENT_3D('',#2212,#2213,#2214);
#2216=PLANE('',#2215);
#2217=CARTESIAN_POINT('',(48.,0.,28.9999999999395));
#2218=DIRECTION('',(0.,0.,1.));
#2219=DIRECTION('',(0.,-1.,0.));
#2220=AXIS2_PLACEMENT_3D('',#2217,#2218,#2219);
#2221=CIRCLE('',#2220,3.23299999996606);
#2222=CARTESIAN_POINT('',(48.,-3.23299999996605,28.9999999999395));
#2223=VERTEX_POINT('',#2222);
#2224=EDGE_CURVE('E114',#2223,#2223,#2221,.T.);
#2225=ORIENTED_EDGE('',*,*,#2224,.F.);
#2226=EDGE_LOOP('',(#2225));
#2227=FACE_BOUND('',#2226,.T.);
#2228=ORIENTED_EDGE('',*,*,#2205,.T.);
#2229=ORIENTED_EDGE('',*,*,#2183,.T.);
#2230=ORIENTED_EDGE('',*,*,#2159,.T.);
#2231=ORIENTED_EDGE('',*,*,#2135,.T.);
#2232=ORIENTED_EDGE('',*,*,#2111,.T.);
#2233=ORIENTED_EDGE('',*,*,#2087,.T.);
#2234=EDGE_LOOP('',(#2228,#2229,#2230,#2231,#2232,#2233));
#2235=FACE_BOUND('',#2234,.T.);
#2236=ADVANCED_FACE('F1001',(#2227,#2235),#2216,.T.);
#2237=CARTESIAN_POINT('',(48.,0.,29.7670000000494));
#2238=DIRECTION('',(0.,0.,1.));
#2239=DIRECTION('',(0.,-1.,0.));
#2240=AXIS2_PLACEMENT_3D('',#2237,#2238,#2239);
#2241=CONICAL_SURFACE('',#2240,4.00000000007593,0.785398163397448);
#2242=ORIENTED_EDGE('',*,*,#2224,.T.);
#2243=EDGE_LOOP('',(#2242));
#2244=FACE_BOUND('',#2243,.T.);
#2245=ORIENTED_EDGE('',*,*,#1870,.F.);
#2246=EDGE_LOOP('',(#2245));
#2247=FACE_BOUND('',#2246,.T.);
#2248=ADVANCED_FACE('F141',(#2244,#2247),#2241,.T.);
#2249=CLOSED_SHELL('',(#35,#55,#75,#95,#115,#135,#173,#195,#215,#261,#281,#463,#734,#754,#786,
#840,#913,#962,#979,#1059,#1115,#1140,#1187,#1207,#1294,#1370,#1408,#1446,#1504,#1620,#1698,
#1736,#1757,#1780,#1796,#1817,#1837,#1857,#1877,#1898,#1918,#1938,#1958,#1978,#1997,#2011,#2067,
#2098,#2122,#2146,#2170,#2194,#2211,#2236,#2248));
#2250=MANIFOLD_SOLID_BREP('B1',#2249);
#2251=ADVANCED_BREP_SHAPE_REPRESENTATION('',(#18,#2250),#14);
#2252=SHAPE_DEFINITION_REPRESENTATION(#9,#2251);
ENDSEC;
END-ISO-10303-21;
